// Mitsubishi GX Works2 project: TR3FB_sample_RDLOOPCmd   PLC: Q03UDV
// TR3FBサンプルプログラム シリアル接続 RDLoopCmd制御

PROGRAM MAIN
VAR
  Initial_1 : P+TAKAYA-TR3-C24_Initial;
  RDLOOPCmd_1 : P+TAKAYA-TR3-C24_RDLOOPCmd;
  SetActionMode_1 : P+TAKAYA-TR3-C24_SetActionMode;
  Response_1 : P+TAKAYA-TR3-C24_Response;
END_VAR
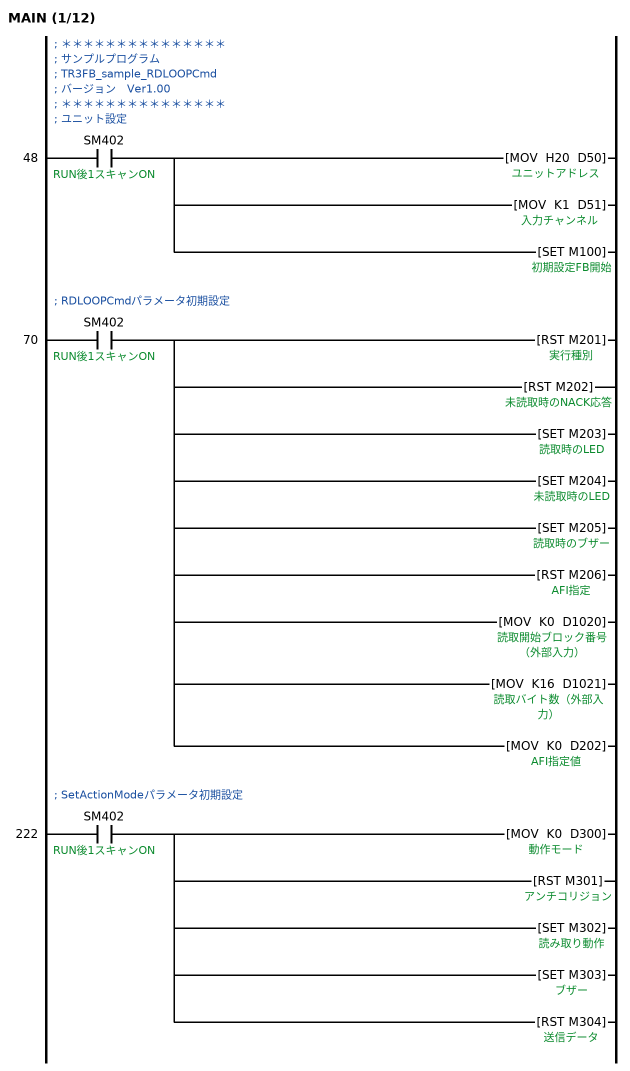
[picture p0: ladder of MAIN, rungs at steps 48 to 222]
; 
; ＊＊＊＊＊＊＊＊＊＊＊＊＊＊＊
; サンプルプログラム
; TR3FB_sample_RDLOOPCmd
; バージョン　Ver1.00
; ＊＊＊＊＊＊＊＊＊＊＊＊＊＊＊
; ユニット設定
48    LD      SM402  ; RUN後1スキャンON
      MOV     H20 D50  ; ユニットアドレス
      MOV     K1 D51  ; 入力チャンネル
      SET     M100  ; 初期設定FB開始
; RDLOOPCmdパラメータ初期設定
70    LD      SM402  ; RUN後1スキャンON
      RST     M201  ; 実行種別
        [note] 実行種別：OFF=RDLOOPモードに遷移
      RST     M202  ; 未読取時のNACK応答
        [note] 未読取時のNACK：OFF=返さない
      SET     M203  ; 読取時のLED
        [note] 読取時LED：ON=点灯
      SET     M204  ; 未読取時のLED
        [note] 未読取時のLED：ON=点灯
      SET     M205  ; 読取時のブザー
        [note] 読取時のブザー：ON=鳴らす
      RST     M206  ; AFI指定
        [note] AFI指定：OFF=AFI値を指定しない
      MOV     K0 D1020  ; 読取開始ブロック番号（外部入力）
        [note] 読取開始ブロック番号=0
      MOV     K16 D1021  ; 読取バイト数（外部入力）
        [note] 読取バイト数=16
      MOV     K0 D202  ; AFI指定値
        [note] AFI指定値=0
; SetActionModeパラメータ初期設定
222   LD      SM402  ; RUN後1スキャンON
      MOV     K0 D300  ; 動作モード
        [note] 動作モード=0x00/コマンドモード
      RST     M301  ; アンチコリジョン
        [note] アンチコリジョン：OFF=無効
      SET     M302  ; 読み取り動作
        [note] 読み取り動作：ON=連続読み取り
      SET     M303  ; ブザー
        [note] ブザー：ON=鳴らす
      RST     M304  ; 送信データ
        [note] 送信データ：OFF=ユーザデータ
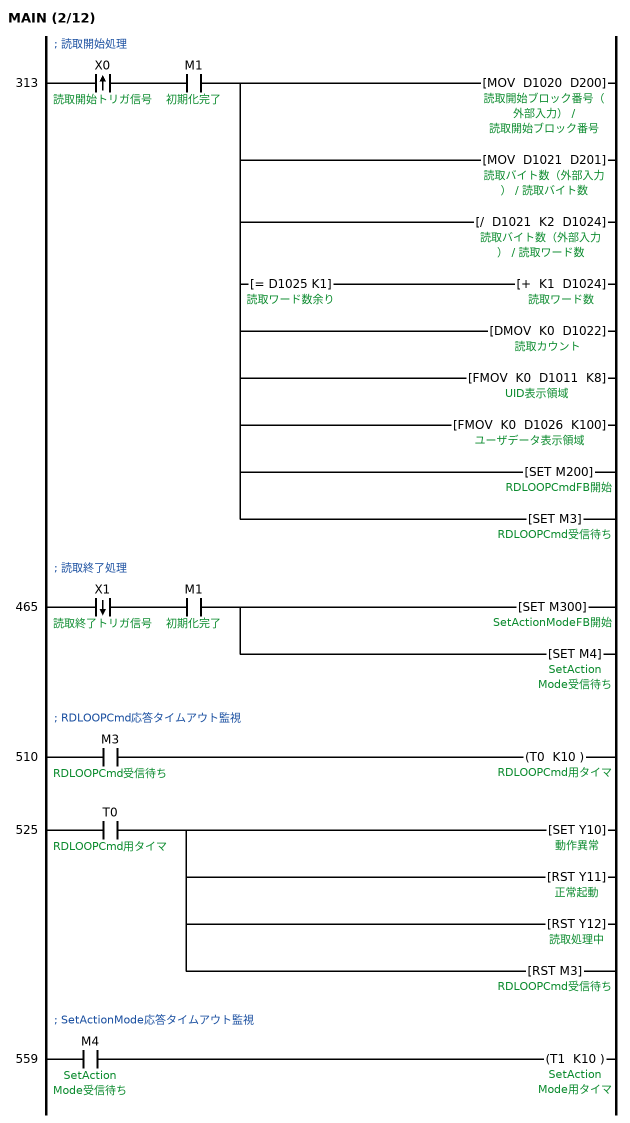
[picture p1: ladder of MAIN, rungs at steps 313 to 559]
; 読取開始処理
313   LDP     X0  ; 読取開始トリガ信号
      AND     M1  ; 初期化完了
      MOV     D1020 D200  ; 読取開始ブロック番号
        [note] 読取開始ブロック番号再設定
      MOV     D1021 D201  ; 読取バイト数
        [note] 読取バイト数再設定
      /       D1021 K2 D1024  ; 読取ワード数
        [note] 読取バイト数から読取ワード数算出
      MPS
      AND=    D1025 K1  ; 読取ワード数余り
      +       K1 D1024
        [note] 余りがあれば1加える
      MPP
      DMOV    K0 D1022  ; 読取カウント
        [note] カウント値クリア
      FMOV    K0 D1011 K8  ; UID表示領域
        [note] UID表示領域クリア
      FMOV    K0 D1026 K100  ; ユーザデータ表示領域
        [note] ユーザデータ表示領域クリア
      SET     M200  ; RDLOOPCmdFB開始
        [note] RDLOOPCmd実行
      SET     M3  ; RDLOOPCmd受信待ち
        [note] 受信待ちフラグセット
; 読取終了処理
465   LDF     X1  ; 読取終了トリガ信号
      AND     M1  ; 初期化完了
      SET     M300  ; SetActionModeFB開始
        [note] SetActionMode実行
      SET     M4  ; SetActionMode受信待ち
        [note] 受信待ちフラグセット
; RDLOOPCmd応答タイムアウト監視
510   LD      M3  ; RDLOOPCmd受信待ち
      OUT     T0 K10  ; RDLOOPCmd用タイマ
        [note] タイマ1秒に設定
525   LD      T0  ; RDLOOPCmd用タイマ
      SET     Y10  ; 動作異常
        [note] タイムアウト処理
      RST     Y11  ; 正常起動
      RST     Y12  ; 読取処理中
      RST     M3  ; RDLOOPCmd受信待ち
; SetActionMode応答タイムアウト監視
559   LD      M4  ; SetActionMode受信待ち
      OUT     T1 K10  ; SetActionMode用タイマ
        [note] タイマ1秒に設定
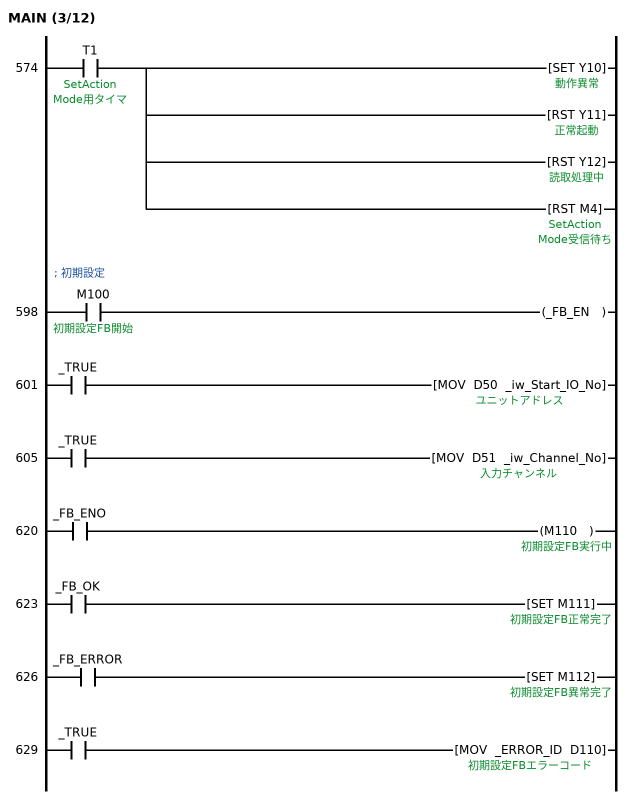
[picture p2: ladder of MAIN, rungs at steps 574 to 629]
574   LD      T1  ; SetActionMode用タイマ
      SET     Y10  ; 動作異常
        [note] タイムアウト処理
      RST     Y11  ; 正常起動
      RST     Y12  ; 読取処理中
      RST     M4  ; SetActionMode受信待ち
; FB BLK START P+TAKAYA-TR3-C24_Initial(Initial_1)
; 
; 初期設定
598   LD      M100  ; 初期設定FB開始
      OUT     _FB_EN
601   LD      _TRUE
      MOV     D50 _iw_Start_IO_No
605   LD      _TRUE
      MOV     D51 _iw_Channel_No
; FB START
; FB_NAME P+TAKAYA-TR3-C24_Initial
; INSTANCE_NAME Initial_1
; FB IN_B:FB_EN
; FB OUT_FB_ENO:B
; FB IN_W:iw_Start_IO_No
; FB OUT_FB_OK:B
; FB IN_W:iw_Channel_No
; FB OUT_FB_ERROR:B
; FB OUT_ERROR_ID:W
; FB END
620   LD      _FB_ENO
      OUT     M110  ; 初期設定FB実行中
623   LD      _FB_OK
      SET     M111  ; 初期設定FB正常完了
626   LD      _FB_ERROR
      SET     M112  ; 初期設定FB異常完了
629   LD      _TRUE
      MOV     _ERROR_ID D110  ; 初期設定FBエラーコード
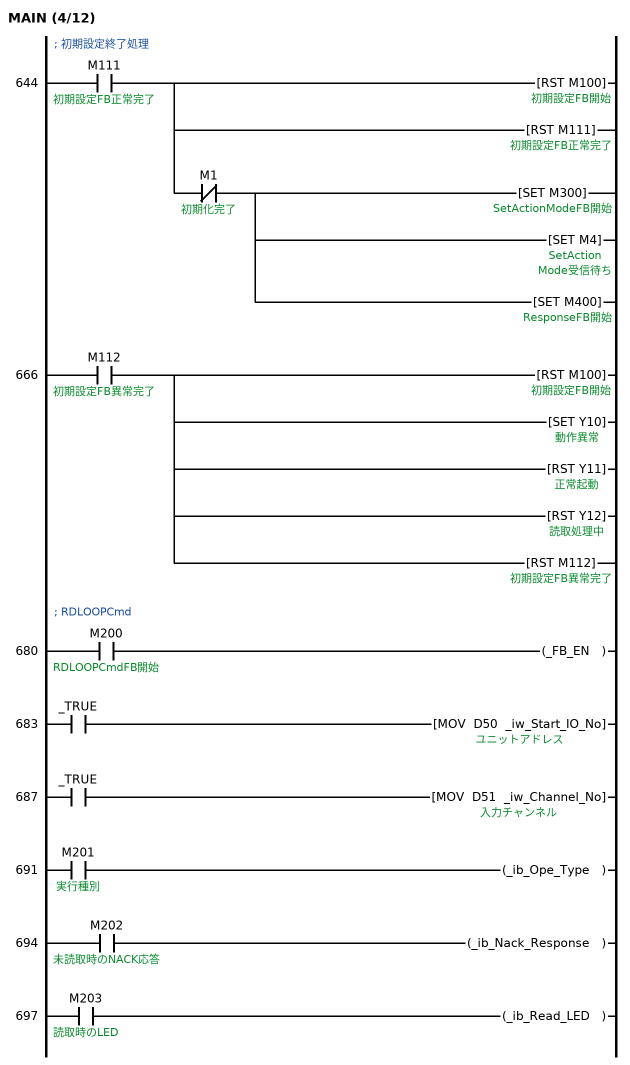
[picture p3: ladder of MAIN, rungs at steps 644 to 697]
; FB BLK END
; 初期設定終了処理
644   LD      M111  ; 初期設定FB正常完了
      RST     M100  ; 初期設定FB開始
      RST     M111  ; 初期設定FB正常完了
      ANI     M1  ; 初期化完了
      SET     M300  ; SetActionModeFB開始
        [note] 起動時コマンドモードに戻す
      SET     M4  ; SetActionMode受信待ち
      SET     M400  ; ResponseFB開始
666   LD      M112  ; 初期設定FB異常完了
      RST     M100  ; 初期設定FB開始
      SET     Y10  ; 動作異常
      RST     Y11  ; 正常起動
      RST     Y12  ; 読取処理中
      RST     M112  ; 初期設定FB異常完了
; FB BLK START P+TAKAYA-TR3-C24_RDLOOPCmd(RDLOOPCmd_1)
; RDLOOPCmd
680   LD      M200  ; RDLOOPCmdFB開始
      OUT     _FB_EN
683   LD      _TRUE
      MOV     D50 _iw_Start_IO_No
687   LD      _TRUE
      MOV     D51 _iw_Channel_No
691   LD      M201  ; 実行種別
      OUT     _ib_Ope_Type
694   LD      M202  ; 未読取時のNACK応答
      OUT     _ib_Nack_Response
697   LD      M203  ; 読取時のLED
      OUT     _ib_Read_LED
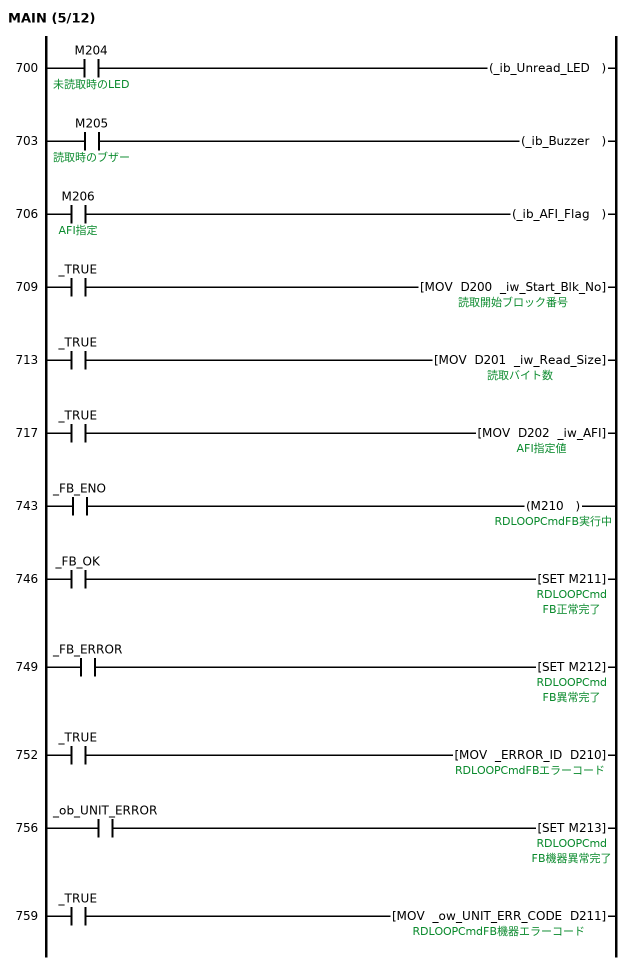
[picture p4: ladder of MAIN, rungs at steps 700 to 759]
700   LD      M204  ; 未読取時のLED
      OUT     _ib_Unread_LED
703   LD      M205  ; 読取時のブザー
      OUT     _ib_Buzzer
706   LD      M206  ; AFI指定
      OUT     _ib_AFI_Flag
709   LD      _TRUE
      MOV     D200 _iw_Start_Blk_No
713   LD      _TRUE
      MOV     D201 _iw_Read_Size
717   LD      _TRUE
      MOV     D202 _iw_AFI
; FB START
; FB_NAME P+TAKAYA-TR3-C24_RDLOOPCmd
; INSTANCE_NAME RDLOOPCmd_1
; FB IN_B:FB_EN
; FB OUT_FB_ENO:B
; FB IN_W:iw_Start_IO_No
; FB OUT_FB_OK:B
; FB IN_W:iw_Channel_No
; FB OUT_FB_ERROR:B
; FB IN_B:ib_Ope_Type
; FB OUT_ERROR_ID:W
; FB IN_B:ib_Nack_Response
; FB OUT_ob_UNIT_ERROR:B
; FB IN_B:ib_Read_LED
; FB OUT_ow_UNIT_ERR_CODE:W
; FB IN_B:ib_Unread_LED
; FB IN_B:ib_Buzzer
; FB IN_B:ib_AFI_Flag
; FB IN_W:iw_Start_Blk_No
; FB IN_W:iw_Read_Size
; FB IN_W:iw_AFI
; FB END
743   LD      _FB_ENO
      OUT     M210  ; RDLOOPCmdFB実行中
746   LD      _FB_OK
      SET     M211  ; RDLOOPCmdFB正常完了
749   LD      _FB_ERROR
      SET     M212  ; RDLOOPCmdFB異常完了
752   LD      _TRUE
      MOV     _ERROR_ID D210  ; RDLOOPCmdFBエラーコード
756   LD      _ob_UNIT_ERROR
      SET     M213  ; RDLOOPCmdFB機器異常完了
759   LD      _TRUE
      MOV     _ow_UNIT_ERR_CODE D211  ; RDLOOPCmdFB機器エラーコード
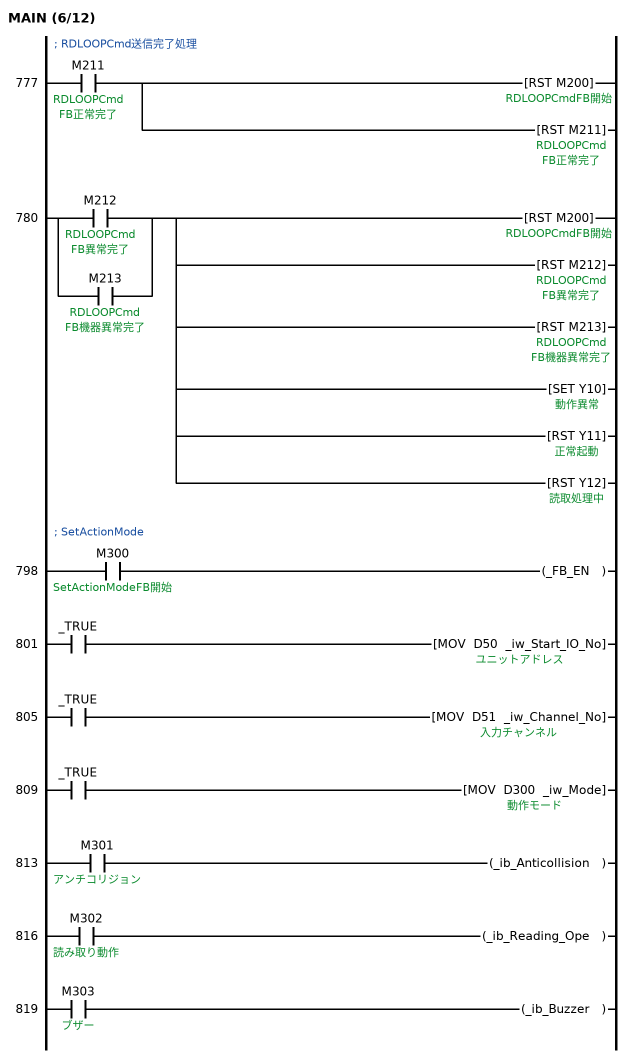
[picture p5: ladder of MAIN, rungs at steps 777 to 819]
; FB BLK END
; RDLOOPCmd送信完了処理
777   LD      M211  ; RDLOOPCmdFB正常完了
      RST     M200  ; RDLOOPCmdFB開始
      RST     M211  ; RDLOOPCmdFB正常完了
780   LD      M212  ; RDLOOPCmdFB異常完了
      OR      M213  ; RDLOOPCmdFB機器異常完了
      RST     M200  ; RDLOOPCmdFB開始
      RST     M212  ; RDLOOPCmdFB異常完了
      RST     M213  ; RDLOOPCmdFB機器異常完了
      SET     Y10  ; 動作異常
      RST     Y11  ; 正常起動
      RST     Y12  ; 読取処理中
; FB BLK START P+TAKAYA-TR3-C24_SetActionMode(SetActionMode_1)
; SetActionMode
798   LD      M300  ; SetActionModeFB開始
      OUT     _FB_EN
801   LD      _TRUE
      MOV     D50 _iw_Start_IO_No
805   LD      _TRUE
      MOV     D51 _iw_Channel_No
809   LD      _TRUE
      MOV     D300 _iw_Mode
813   LD      M301  ; アンチコリジョン
      OUT     _ib_Anticollision
816   LD      M302  ; 読み取り動作
      OUT     _ib_Reading_Ope
819   LD      M303  ; ブザー
      OUT     _ib_Buzzer
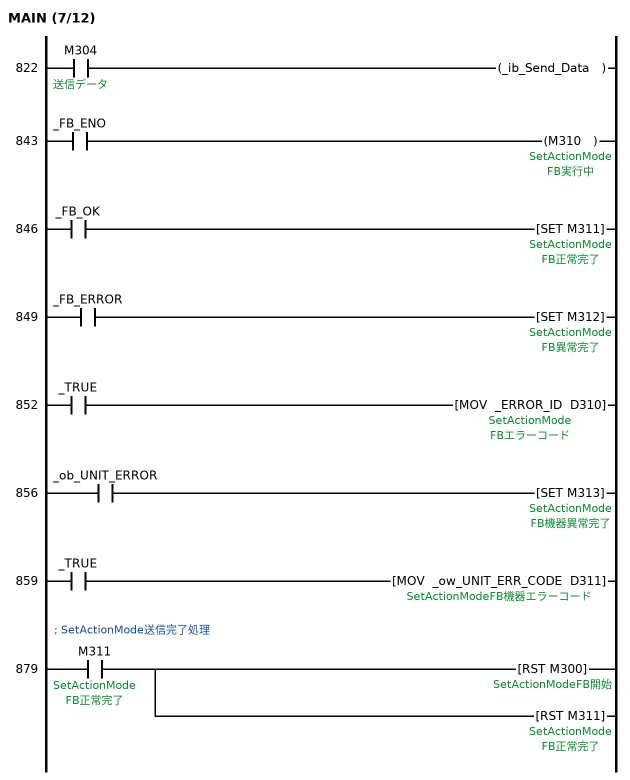
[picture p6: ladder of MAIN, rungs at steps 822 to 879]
822   LD      M304  ; 送信データ
      OUT     _ib_Send_Data
; FB START
; FB_NAME P+TAKAYA-TR3-C24_SetActionMode
; INSTANCE_NAME SetActionMode_1
; FB IN_B:FB_EN
; FB OUT_FB_ENO:B
; FB IN_W:iw_Start_IO_No
; FB OUT_FB_OK:B
; FB IN_W:iw_Channel_No
; FB OUT_FB_ERROR:B
; FB IN_W:iw_Mode
; FB OUT_ERROR_ID:W
; FB IN_B:ib_Anticollision
; FB OUT_ob_UNIT_ERROR:B
; FB IN_B:ib_Reading_Ope
; FB OUT_ow_UNIT_ERR_CODE:W
; FB IN_B:ib_Buzzer
; FB IN_B:ib_Send_Data
; FB END
843   LD      _FB_ENO
      OUT     M310  ; SetActionModeFB実行中
846   LD      _FB_OK
      SET     M311  ; SetActionModeFB正常完了
849   LD      _FB_ERROR
      SET     M312  ; SetActionModeFB異常完了
852   LD      _TRUE
      MOV     _ERROR_ID D310  ; SetActionModeFBエラーコード
856   LD      _ob_UNIT_ERROR
      SET     M313  ; SetActionModeFB機器異常完了
859   LD      _TRUE
      MOV     _ow_UNIT_ERR_CODE D311  ; SetActionModeFB機器エラーコード
; FB BLK END
; SetActionMode送信完了処理
879   LD      M311  ; SetActionModeFB正常完了
      RST     M300  ; SetActionModeFB開始
      RST     M311  ; SetActionModeFB正常完了
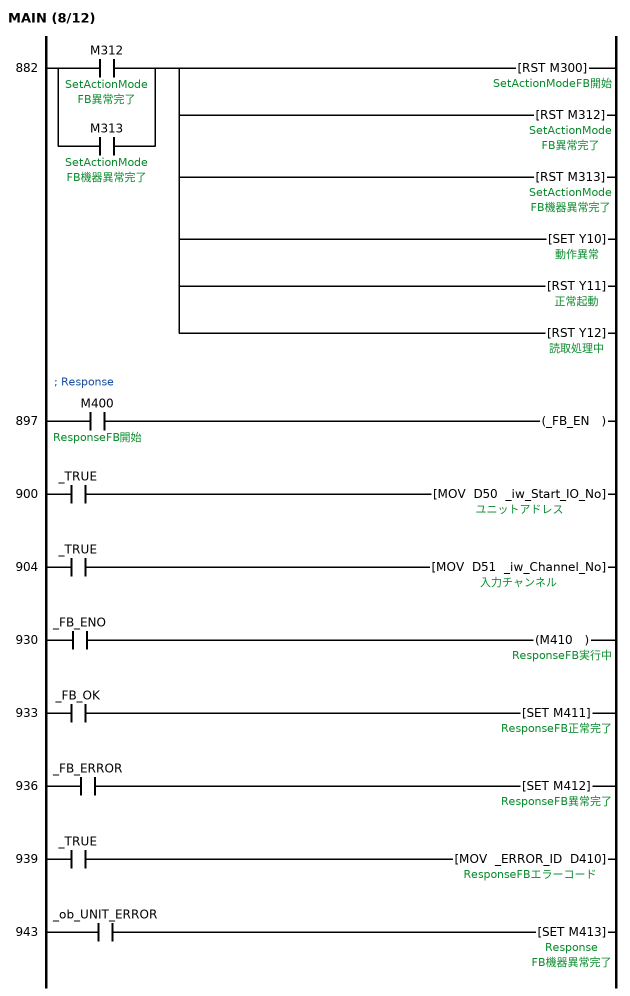
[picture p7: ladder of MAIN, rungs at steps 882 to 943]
882   LD      M312  ; SetActionModeFB異常完了
      OR      M313  ; SetActionModeFB機器異常完了
      RST     M300  ; SetActionModeFB開始
      RST     M312  ; SetActionModeFB異常完了
      RST     M313  ; SetActionModeFB機器異常完了
      SET     Y10  ; 動作異常
      RST     Y11  ; 正常起動
      RST     Y12  ; 読取処理中
; FB BLK START P+TAKAYA-TR3-C24_Response(Response_1)
; Response
897   LD      M400  ; ResponseFB開始
      OUT     _FB_EN
900   LD      _TRUE
      MOV     D50 _iw_Start_IO_No
904   LD      _TRUE
      MOV     D51 _iw_Channel_No
; FB START
; FB_NAME P+TAKAYA-TR3-C24_Response
; INSTANCE_NAME Response_1
; FB IN_B:FB_EN
; FB OUT_FB_ENO:B
; FB IN_W:iw_Start_IO_No
; FB OUT_FB_OK:B
; FB IN_W:iw_Channel_No
; FB OUT_FB_ERROR:B
; FB OUT_ERROR_ID:W
; FB OUT_ob_UNIT_ERROR:B
; FB OUT_ow_UNT_ERR_CODE1:W
; FB OUT_ow_UNT_ERR_CODE2:W
; FB OUT_ow_RFID_Res_Type:W
; FB OUT_ow_RFID_ID:W
; FB OUT_ow_RFID_UID_Len:W
; FB OUT_ow_RFID_Data_Len:W
; FB OUT_ow_RFID_UII_Len:W
; FB OUT_owa_RFID_UID:W
; FB OUT_owa_RFID_Data:W
; FB OUT_owa_RFID_UII:W
; FB END
930   LD      _FB_ENO
      OUT     M410  ; ResponseFB実行中
933   LD      _FB_OK
      SET     M411  ; ResponseFB正常完了
936   LD      _FB_ERROR
      SET     M412  ; ResponseFB異常完了
939   LD      _TRUE
      MOV     _ERROR_ID D410  ; ResponseFBエラーコード
943   LD      _ob_UNIT_ERROR
      SET     M413  ; ResponseFB機器異常完了
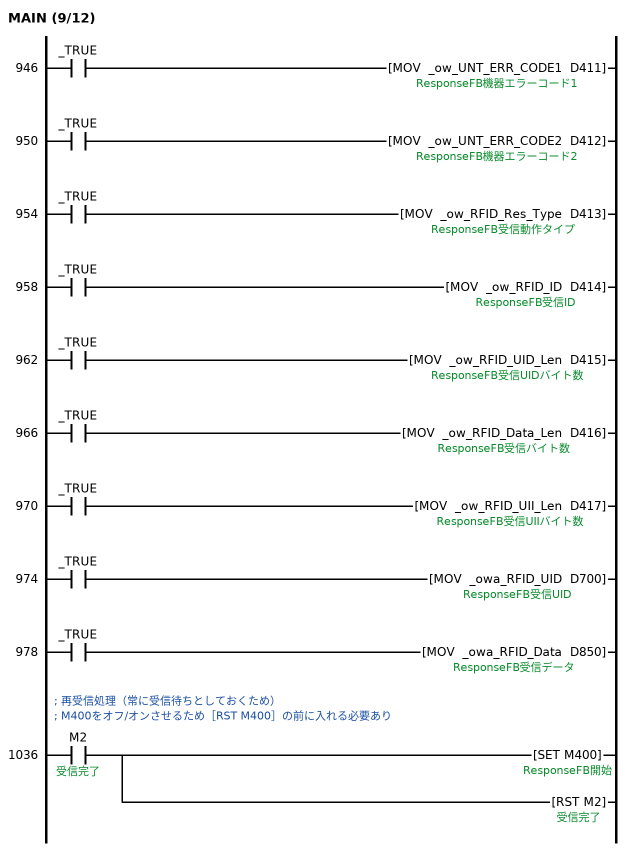
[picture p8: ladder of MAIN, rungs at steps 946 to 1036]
946   LD      _TRUE
      MOV     _ow_UNT_ERR_CODE1 D411  ; ResponseFB機器エラーコード1
950   LD      _TRUE
      MOV     _ow_UNT_ERR_CODE2 D412  ; ResponseFB機器エラーコード2
954   LD      _TRUE
      MOV     _ow_RFID_Res_Type D413  ; ResponseFB受信動作タイプ
958   LD      _TRUE
      MOV     _ow_RFID_ID D414  ; ResponseFB受信ID
962   LD      _TRUE
      MOV     _ow_RFID_UID_Len D415  ; ResponseFB受信UIDバイト数
966   LD      _TRUE
      MOV     _ow_RFID_Data_Len D416  ; ResponseFB受信バイト数
970   LD      _TRUE
      MOV     _ow_RFID_UII_Len D417  ; ResponseFB受信UIIバイト数
974   LD      _TRUE
      MOV     _owa_RFID_UID D700  ; ResponseFB受信UID
978   LD      _TRUE
      MOV     _owa_RFID_Data D850  ; ResponseFB受信データ
; FB BLK END
; 再受信処理（常に受信待ちとしておくため）
; M400をオフ/オンさせるため［RST M400］の前に入れる必要あり
1036  LD      M2  ; 受信完了
      SET     M400  ; ResponseFB開始
      RST     M2  ; 受信完了
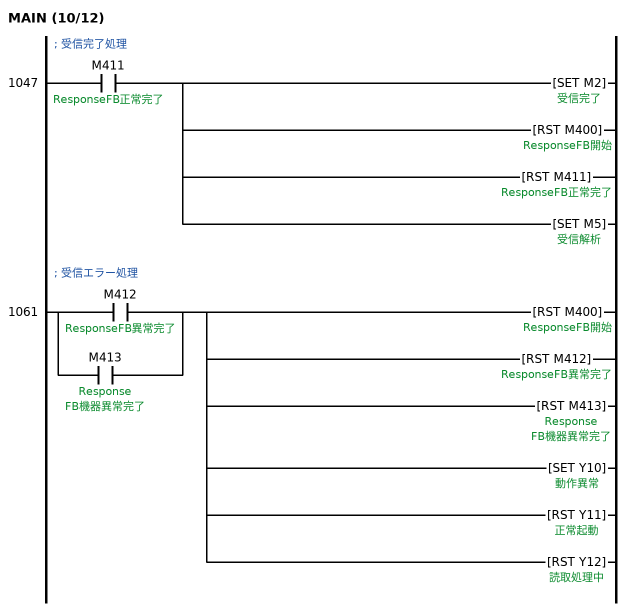
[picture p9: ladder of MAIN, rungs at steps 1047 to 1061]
; 受信完了処理
1047  LD      M411  ; ResponseFB正常完了
      SET     M2  ; 受信完了
      RST     M400  ; ResponseFB開始
      RST     M411  ; ResponseFB正常完了
      SET     M5  ; 受信解析
; 受信エラー処理
1061  LD      M412  ; ResponseFB異常完了
      OR      M413  ; ResponseFB機器異常完了
      RST     M400  ; ResponseFB開始
      RST     M412  ; ResponseFB異常完了
      RST     M413  ; ResponseFB機器異常完了
      SET     Y10  ; 動作異常
      RST     Y11  ; 正常起動
      RST     Y12  ; 読取処理中
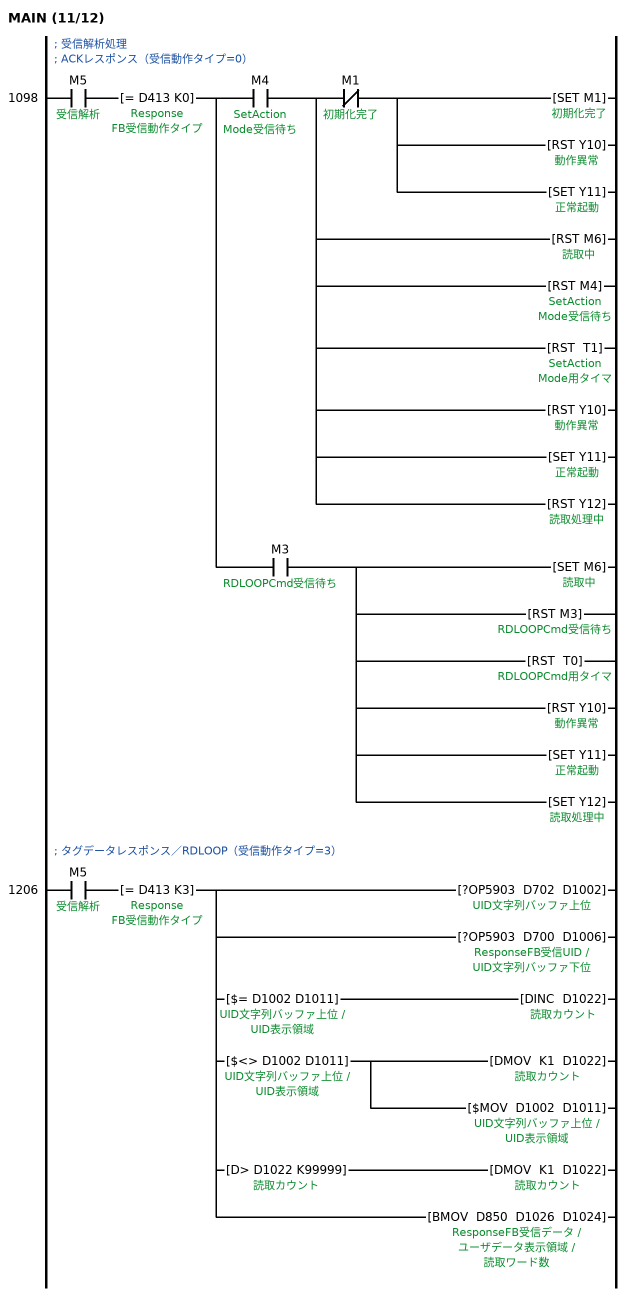
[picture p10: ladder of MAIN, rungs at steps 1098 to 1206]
; 
; 受信解析処理
; ACKレスポンス（受信動作タイプ=0）
1098  LD      M5  ; 受信解析
      AND=    D413 K0  ; ResponseFB受信動作タイプ
      MPS
      AND     M4  ; SetActionMode受信待ち
      MPS
      ANI     M1  ; 初期化完了
      SET     M1  ; 初期化完了
        [note] SetActionModeのACK
      RST     Y10  ; 動作異常
      SET     Y11  ; 正常起動
      MPP
      RST     M6  ; 読取中
      RST     M4  ; SetActionMode受信待ち
      RST     T1  ; SetActionMode用タイマ
        [note] 正常処理のためタイマクリア
      RST     Y10  ; 動作異常
      SET     Y11  ; 正常起動
      RST     Y12  ; 読取処理中
      MPP
      AND     M3  ; RDLOOPCmd受信待ち
      SET     M6  ; 読取中
        [note] RDLOOPCmdのACK
      RST     M3  ; RDLOOPCmd受信待ち
      RST     T0  ; RDLOOPCmd用タイマ
        [note] 正常処理のためタイマクリア
      RST     Y10  ; 動作異常
      SET     Y11  ; 正常起動
      SET     Y12  ; 読取処理中
; タグデータレスポンス／RDLOOP（受信動作タイプ=3）
1206  LD      M5  ; 受信解析
      AND=    D413 K3  ; ResponseFB受信動作タイプ
      ?OP5903 D702 D1002  ; UID文字列バッファ上位
        [note] UID上位をHEX文字列でGOTに表示
      ?OP5903 D700 D1006  ; UID文字列バッファ下位
        [note] UID下位をHEX文字列でGOTに表示
      MPS
      AND$=   D1002 D1011  ; UID文字列バッファ上位 / UID表示領域
      DINC    D1022
        [note] UIDが同じならカウント数インクリ
      MRD
      AND$<>  D1002 D1011  ; UID文字列バッファ上位 / UID表示領域
      DMOV    K1 D1022
        [note] UIDが異なる場合カウント値=1
      $MOV    D1002 D1011
        [note] UIDデータをHEX文字列でGOTに表示
      MRD
      ANDD>   D1022 K99999  ; 読取カウント
      DMOV    K1 D1022
        [note] カウント値>99999で1にリセット
      MPP
      BMOV    D850 D1026 D1024
        [note] ユーザデータ表示
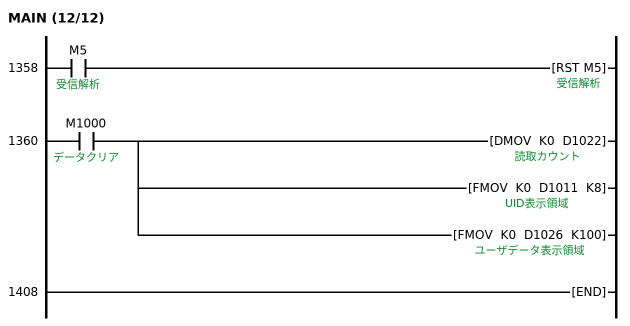
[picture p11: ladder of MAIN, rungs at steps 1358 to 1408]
1358  LD      M5  ; 受信解析
      RST     M5  ; 受信解析
1360  LD      M1000  ; データクリア
      DMOV    K0 D1022
        [note] カウント値クリア
      FMOV    K0 D1011 K8
        [note] UID表示領域クリア
      FMOV    K0 D1026 K100
        [note] ユーザデータ表示領域クリア
1408  END
END_PROGRAM

FUNCTION_BLOCK P+TAKAYA-TR3-C24_Initial  // 初期設定
VAR_INPUT
  FB_EN : BOOL;  (* 実行命令 *)
  iw_Start_IO_No : INT;  (* ユニット装着XYアドレス *)
  iw_Channel_No : INT;  (* 入力チャンネル *)
END_VAR
VAR_OUTPUT
  FB_ENO : BOOL;  (* 実行状態 *)
  FB_OK : BOOL;  (* 正常完了 *)
  FB_ERROR : BOOL;  (* 異常完了フラグ *)
  ERROR_ID : INT;  (* エラーコード *)
END_VAR
VAR
  vb_Program_Init : BOOL;  (* プログラム実行前初期化 *)
  vb_Check_Input : BOOL;  (* 入力範囲判定 *)
  vb_Module_Init : BOOL;  (* ユニット初期化 *)
  vb_Program_End : BOOL;  (* FB終了処理内部フラグ *)
  vb_Tmp_OK : BOOL;  (* FB完了内部フラグ *)
  vb_Tmp_Error : BOOL;  (* エラー内部フラグ *)
  vw_Start_IO_No_Tmp : INT;  (* ユニット装着XYアドレス内部 *)
  vw_Channel_No_Tmp : INT;  (* 入力チャンネル内部 *)
  vw_ZTmp1 : INT;  (* Zデバイス1内部 *)
  vw_ZTmp2 : INT;  (* Zデバイス2内部 *)
END_VAR
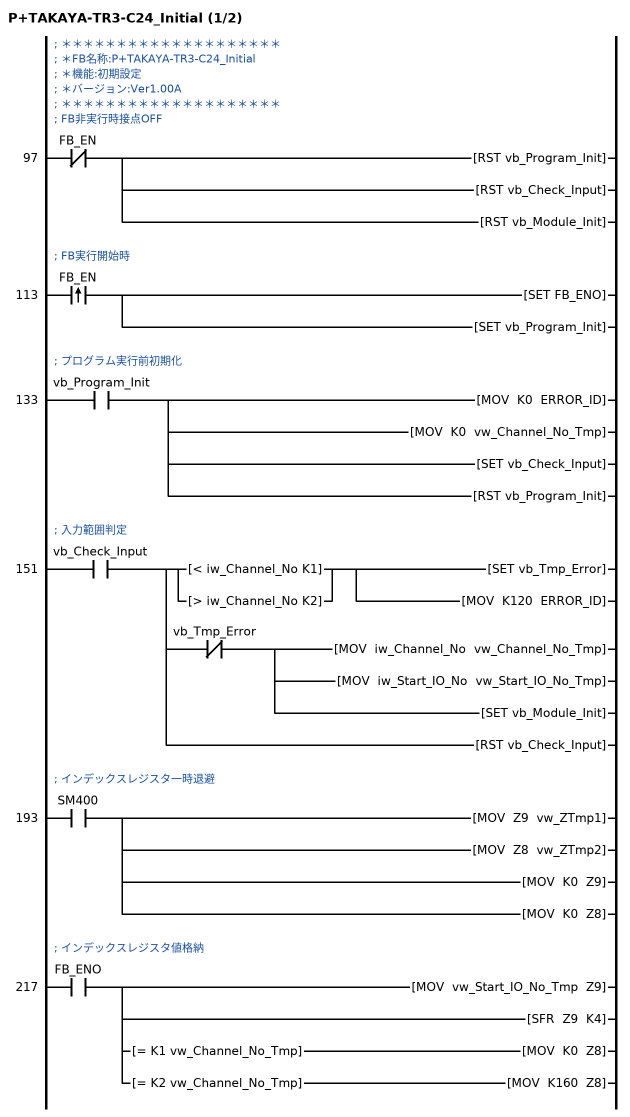
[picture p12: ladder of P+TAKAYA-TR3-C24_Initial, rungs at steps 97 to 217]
; ＊＊＊＊＊＊＊＊＊＊＊＊＊＊＊＊＊＊＊＊
; ＊FB名称:P+TAKAYA-TR3-C24_Initial
; ＊機能:初期設定
; ＊バージョン:Ver1.00A
; ＊＊＊＊＊＊＊＊＊＊＊＊＊＊＊＊＊＊＊＊
; FB非実行時接点OFF
97    LDI     FB_EN
      RST     vb_Program_Init
      RST     vb_Check_Input
      RST     vb_Module_Init
; FB実行開始時
113   LDP     FB_EN
      SET     FB_ENO
      SET     vb_Program_Init
; プログラム実行前初期化
133   LD      vb_Program_Init
      MOV     K0 ERROR_ID
      MOV     K0 vw_Channel_No_Tmp
      SET     vb_Check_Input
      RST     vb_Program_Init
; 入力範囲判定
151   LD      vb_Check_Input
      MPS
      LD<     iw_Channel_No K1
      OR>     iw_Channel_No K2
      ANB
      SET     vb_Tmp_Error
      MOV     K120 ERROR_ID
      MRD
      ANI     vb_Tmp_Error
      MOV     iw_Channel_No vw_Channel_No_Tmp
      MOV     iw_Start_IO_No vw_Start_IO_No_Tmp
      SET     vb_Module_Init
      MPP
      RST     vb_Check_Input
; インデックスレジスタ一時退避
193   LD      SM400
      MOV     Z9 vw_ZTmp1
      MOV     Z8 vw_ZTmp2
      MOV     K0 Z9
      MOV     K0 Z8
; インデックスレジスタ値格納
217   LD      FB_ENO
      MOV     vw_Start_IO_No_Tmp Z9
      SFR     Z9 K4
      MPS
      AND=    K1 vw_Channel_No_Tmp
      MOV     K0 Z8
      MPP
      AND=    K2 vw_Channel_No_Tmp
      MOV     K160 Z8
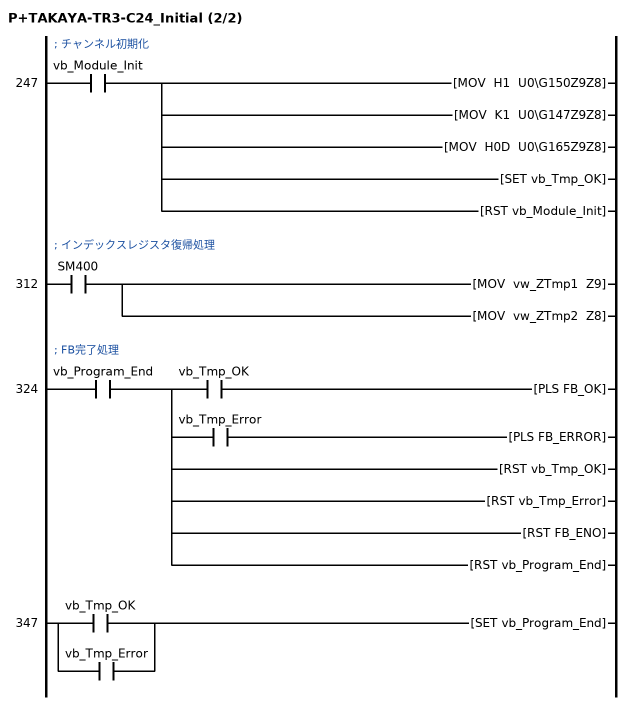
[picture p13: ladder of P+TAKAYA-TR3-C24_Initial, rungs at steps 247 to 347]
; チャンネル初期化
247   LD      vb_Module_Init
      MOV     H1 U0\G150Z9Z8
        [note] バイト単位指定
      MOV     K1 U0\G147Z9Z8
        [note] DC制御指定
      MOV     H0D U0\G165Z9Z8
        [note] 受信終了コード
      SET     vb_Tmp_OK
      RST     vb_Module_Init
; インデックスレジスタ復帰処理
312   LD      SM400
      MOV     vw_ZTmp1 Z9
      MOV     vw_ZTmp2 Z8
; FB完了処理
324   LD      vb_Program_End
      MPS
      AND     vb_Tmp_OK
      PLS     FB_OK
      MRD
      AND     vb_Tmp_Error
      PLS     FB_ERROR
      MPP
      RST     vb_Tmp_OK
      RST     vb_Tmp_Error
      RST     FB_ENO
      RST     vb_Program_End
347   LD      vb_Tmp_OK
      OR      vb_Tmp_Error
      SET     vb_Program_End
END_FUNCTION_BLOCK

FUNCTION_BLOCK P+TAKAYA-TR3-C24_RDLOOPCmd  // RDLOOPCmd
VAR_INPUT
  FB_EN : BOOL;  (* 実行命令 *)
END_VAR
VAR_OUTPUT
  FB_OK : BOOL;  (* 正常完了 *)
  FB_ERROR : BOOL;  (* 異常完了フラグ *)
  ERROR_ID : INT;  (* エラーコード *)
  FB_ENO : BOOL;  (* 実行状態 *)
END_VAR
VAR
  vb_Program_Init : BOOL;  (* プログラム実行前初期化 *)
  vb_Check_Input : BOOL;  (* 入力範囲判定 *)
  vb_Tmp_Error : BOOL;  (* エラー内部フラグ *)
  vb_Tmp_OK : BOOL;  (* FB完了内部フラグ *)
  vb_Tmp_Unit_Error : BOOL;  (* 機器エラー内部フラグ *)
  vb_Program_End : BOOL;  (* FB終了処理内部フラグ *)
END_VAR
VAR_OUTPUT
  ob_UNIT_ERROR : BOOL;  (* 機器異常完了フラグ *)
  ow_UNIT_ERR_CODE : INT;  (* 機器エラーコード *)
END_VAR
VAR
  vwa_Control_Data : ARRAY [0..2] OF INT;  (* コントロールデータ *)
  vb_Sum_Calc : BOOL;  (* SUM計算開始フラグ *)
  vb_Send_Ready : BOOL;  (* 送信準備完了フラグ *)
  vwa_Send_Sum : ARRAY [0..1] OF INT;  (* 送信SUM合計値 *)
  vwa_Buff_Send_Byte : ARRAY [0..12] OF INT;  (* 送信バッファバイト *)
  vba_Send : ARRAY [0..2] OF BOOL;  (* 送信処理フラグ *)
END_VAR
VAR_INPUT
  iw_Start_Blk_No : INT;  (* 読み取り開始ブロック番号 *)
END_VAR
VAR
  vw_Cmd_Parameter : INT;  (* コマンドパラメータ *)
  vb_Cmd_Parameter : BOOL;  (* コマンドパラメータ設定 *)
  vw_Start_Blk_No_Tmp : INT;  (* 読み取り開始ブロック番号内部 *)
  vb_Join_Byte : BOOL;  (* バイト単位結合 *)
  vwa_Buff_Send_Word : ARRAY [0..6] OF INT;  (* 送信バッファワード *)
END_VAR
VAR_INPUT
  iw_Read_Size : INT;  (* 読み取りバイト数 *)
END_VAR
VAR
  vw_Read_Size_Tmp : INT;  (* 読み取りバイト数内部 *)
END_VAR
VAR_INPUT
  iw_AFI : INT;  (* AFI指定値 *)
END_VAR
VAR
  vw_AFI_Tmp : INT;  (* AFI指定値内部 *)
END_VAR
VAR_INPUT
  ib_Ope_Type : BOOL;  (* 実行種別 *)
  ib_Nack_Response : BOOL;  (* 未読み取り時のNACK応答 *)
  ib_Read_LED : BOOL;  (* 読み取り時のLED *)
  ib_Unread_LED : BOOL;  (* 未読み取り時のLED *)
  ib_Buzzer : BOOL;  (* 読み取り時のブザー *)
  ib_AFI_Flag : BOOL;  (* AFI指定 *)
END_VAR
VAR
  vb_RFID_Option : BOOL;  (* RFタグオプションフラグ *)
  vw_RFID_Option_Tmp : INT;  (* RFタグオプション *)
END_VAR
VAR_INPUT
  iw_Start_IO_No : INT;  (* ユニット装着XYアドレス *)
  iw_Channel_No : INT;  (* 入力チャンネル *)
END_VAR
VAR
  vw_Start_IO_No_Tmp : INT;  (* ユニット装着XYアドレス内部 *)
  vw_Channel_No_Tmp : INT;  (* 入力チャンネル内部 *)
  vw_ZTmp1 : INT;  (* Zデバイス1内部 *)
  vb_Make_Control_Data : BOOL;  (* コントロールデータ生成 *)
END_VAR
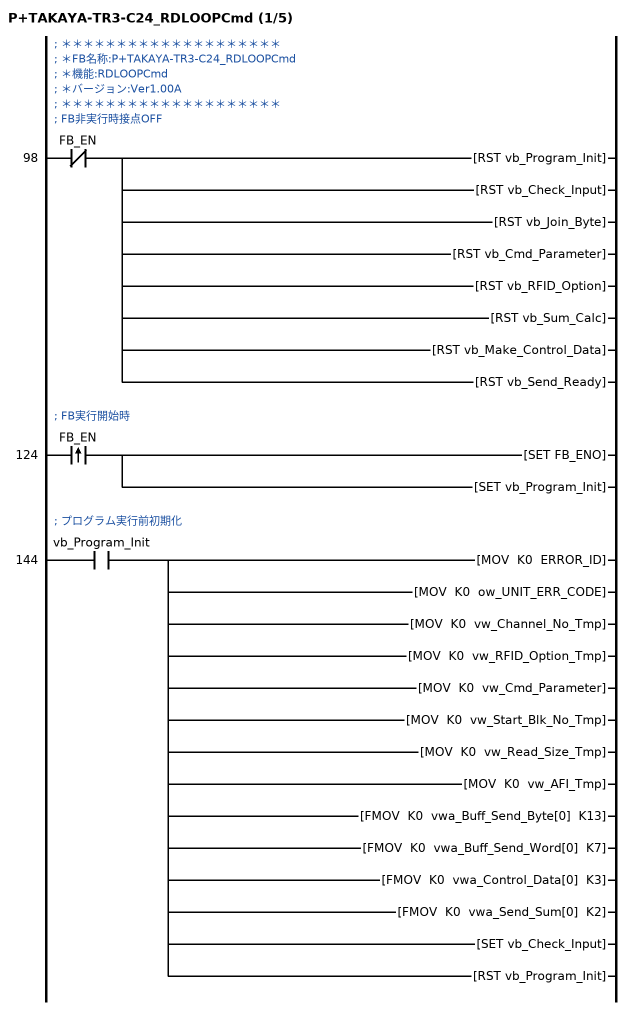
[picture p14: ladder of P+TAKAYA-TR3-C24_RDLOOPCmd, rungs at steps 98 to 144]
; ＊＊＊＊＊＊＊＊＊＊＊＊＊＊＊＊＊＊＊＊
; ＊FB名称:P+TAKAYA-TR3-C24_RDLOOPCmd
; ＊機能:RDLOOPCmd
; ＊バージョン:Ver1.00A
; ＊＊＊＊＊＊＊＊＊＊＊＊＊＊＊＊＊＊＊＊
; FB非実行時接点OFF
98    LDI     FB_EN
      RST     vb_Program_Init
      RST     vb_Check_Input
      RST     vb_Join_Byte
      RST     vb_Cmd_Parameter
      RST     vb_RFID_Option
      RST     vb_Sum_Calc
      RST     vb_Make_Control_Data
      RST     vb_Send_Ready
; FB実行開始時
124   LDP     FB_EN
      SET     FB_ENO
      SET     vb_Program_Init
; プログラム実行前初期化
144   LD      vb_Program_Init
      MOV     K0 ERROR_ID
      MOV     K0 ow_UNIT_ERR_CODE
      MOV     K0 vw_Channel_No_Tmp
      MOV     K0 vw_RFID_Option_Tmp
      MOV     K0 vw_Cmd_Parameter
      MOV     K0 vw_Start_Blk_No_Tmp
      MOV     K0 vw_Read_Size_Tmp
      MOV     K0 vw_AFI_Tmp
      FMOV    K0 vwa_Buff_Send_Byte[0] K13
      FMOV    K0 vwa_Buff_Send_Word[0] K7
      FMOV    K0 vwa_Control_Data[0] K3
      FMOV    K0 vwa_Send_Sum[0] K2
      SET     vb_Check_Input
      RST     vb_Program_Init
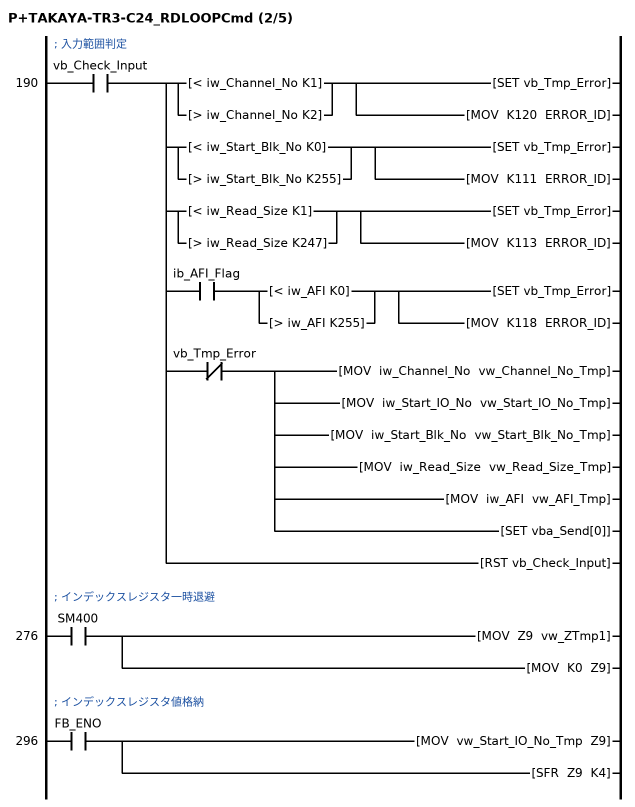
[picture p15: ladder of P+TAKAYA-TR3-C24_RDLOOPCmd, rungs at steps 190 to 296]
; 入力範囲判定
190   LD      vb_Check_Input
      MPS
      LD<     iw_Channel_No K1
      OR>     iw_Channel_No K2
      ANB
      SET     vb_Tmp_Error
      MOV     K120 ERROR_ID
      MRD
      LD<     iw_Start_Blk_No K0
      OR>     iw_Start_Blk_No K255
      ANB
      SET     vb_Tmp_Error
      MOV     K111 ERROR_ID
      MRD
      LD<     iw_Read_Size K1
      OR>     iw_Read_Size K247
      ANB
      SET     vb_Tmp_Error
      MOV     K113 ERROR_ID
      MRD
      AND     ib_AFI_Flag
      LD<     iw_AFI K0
      OR>     iw_AFI K255
      ANB
      SET     vb_Tmp_Error
      MOV     K118 ERROR_ID
      MRD
      ANI     vb_Tmp_Error
      MOV     iw_Channel_No vw_Channel_No_Tmp
      MOV     iw_Start_IO_No vw_Start_IO_No_Tmp
      MOV     iw_Start_Blk_No vw_Start_Blk_No_Tmp
      MOV     iw_Read_Size vw_Read_Size_Tmp
      MOV     iw_AFI vw_AFI_Tmp
      SET     vba_Send[0]
      MPP
      RST     vb_Check_Input
; インデックスレジスタ一時退避
276   LD      SM400
      MOV     Z9 vw_ZTmp1
      MOV     K0 Z9
; インデックスレジスタ値格納
296   LD      FB_ENO
      MOV     vw_Start_IO_No_Tmp Z9
      SFR     Z9 K4
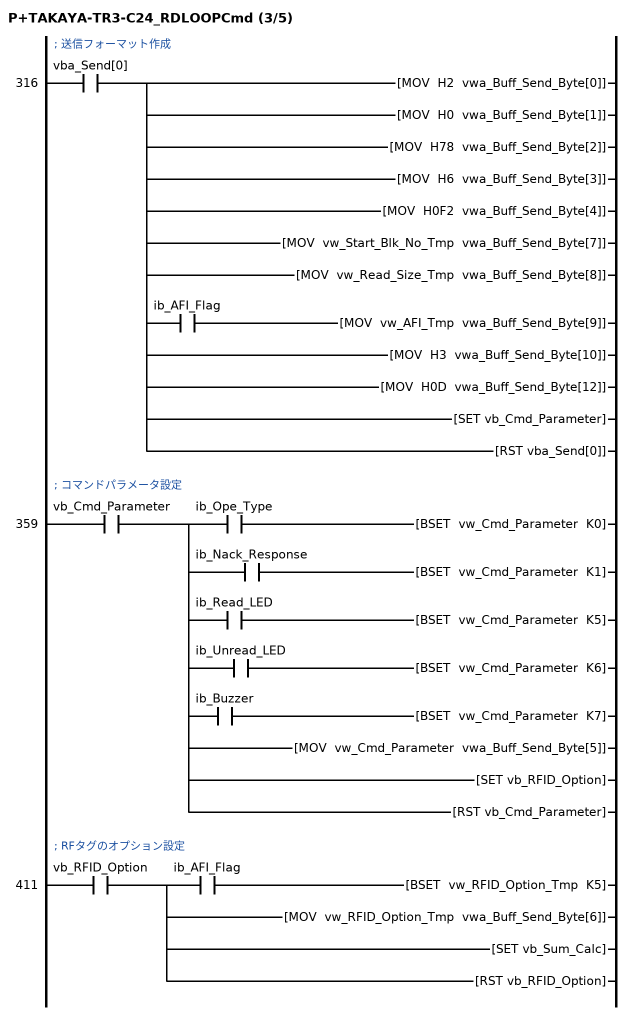
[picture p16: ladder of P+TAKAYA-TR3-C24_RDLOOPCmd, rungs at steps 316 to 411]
; 送信フォーマット作成
316   LD      vba_Send[0]
      MOV     H2 vwa_Buff_Send_Byte[0]
      MOV     H0 vwa_Buff_Send_Byte[1]
      MOV     H78 vwa_Buff_Send_Byte[2]
      MOV     H6 vwa_Buff_Send_Byte[3]
      MOV     H0F2 vwa_Buff_Send_Byte[4]
      MOV     vw_Start_Blk_No_Tmp vwa_Buff_Send_Byte[7]
      MOV     vw_Read_Size_Tmp vwa_Buff_Send_Byte[8]
      MPS
      AND     ib_AFI_Flag
      MOV     vw_AFI_Tmp vwa_Buff_Send_Byte[9]
      MPP
      MOV     H3 vwa_Buff_Send_Byte[10]
      MOV     H0D vwa_Buff_Send_Byte[12]
      SET     vb_Cmd_Parameter
      RST     vba_Send[0]
; コマンドパラメータ設定
359   LD      vb_Cmd_Parameter
      MPS
      AND     ib_Ope_Type
      BSET    vw_Cmd_Parameter K0
      MRD
      AND     ib_Nack_Response
      BSET    vw_Cmd_Parameter K1
      MRD
      AND     ib_Read_LED
      BSET    vw_Cmd_Parameter K5
      MRD
      AND     ib_Unread_LED
      BSET    vw_Cmd_Parameter K6
      MRD
      AND     ib_Buzzer
      BSET    vw_Cmd_Parameter K7
      MPP
      MOV     vw_Cmd_Parameter vwa_Buff_Send_Byte[5]
      SET     vb_RFID_Option
      RST     vb_Cmd_Parameter
; RFタグのオプション設定
411   LD      vb_RFID_Option
      MPS
      AND     ib_AFI_Flag
      BSET    vw_RFID_Option_Tmp K5
      MPP
      MOV     vw_RFID_Option_Tmp vwa_Buff_Send_Byte[6]
      SET     vb_Sum_Calc
      RST     vb_RFID_Option
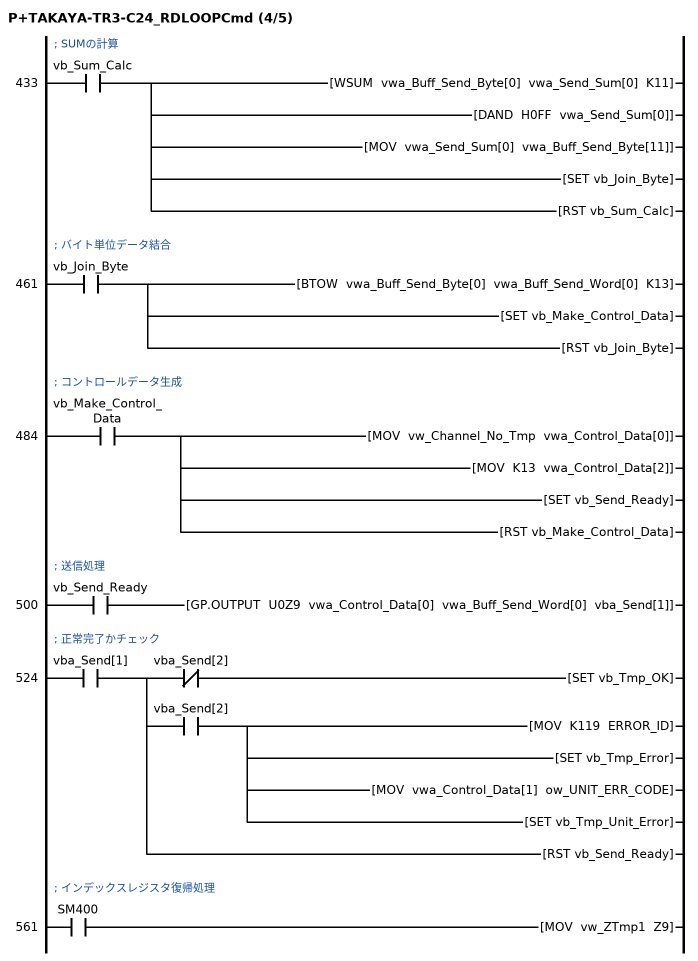
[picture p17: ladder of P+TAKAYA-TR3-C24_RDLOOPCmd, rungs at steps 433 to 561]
; SUMの計算
433   LD      vb_Sum_Calc
      WSUM    vwa_Buff_Send_Byte[0] vwa_Send_Sum[0] K11
      DAND    H0FF vwa_Send_Sum[0]
      MOV     vwa_Send_Sum[0] vwa_Buff_Send_Byte[11]
      SET     vb_Join_Byte
      RST     vb_Sum_Calc
; バイト単位データ結合
461   LD      vb_Join_Byte
      BTOW    vwa_Buff_Send_Byte[0] vwa_Buff_Send_Word[0] K13
      SET     vb_Make_Control_Data
      RST     vb_Join_Byte
; コントロールデータ生成
484   LD      vb_Make_Control_Data
      MOV     vw_Channel_No_Tmp vwa_Control_Data[0]
      MOV     K13 vwa_Control_Data[2]
      SET     vb_Send_Ready
      RST     vb_Make_Control_Data
; 送信処理
500   LD      vb_Send_Ready
      GP.OUTPUT U0Z9 vwa_Control_Data[0] vwa_Buff_Send_Word[0] vba_Send[1]
; 正常完了かチェック
524   LD      vba_Send[1]
      MPS
      ANI     vba_Send[2]
      SET     vb_Tmp_OK
      MRD
      AND     vba_Send[2]
      MOV     K119 ERROR_ID
      SET     vb_Tmp_Error
      MOV     vwa_Control_Data[1] ow_UNIT_ERR_CODE
      SET     vb_Tmp_Unit_Error
      MPP
      RST     vb_Send_Ready
; インデックスレジスタ復帰処理
561   LD      SM400
      MOV     vw_ZTmp1 Z9
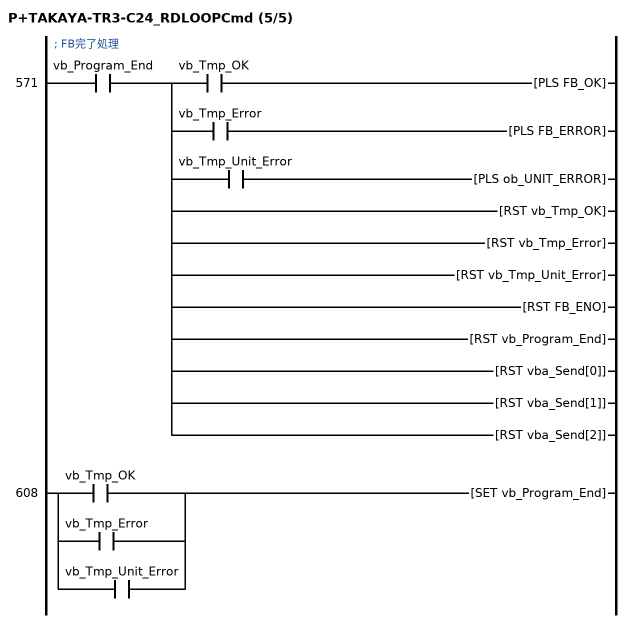
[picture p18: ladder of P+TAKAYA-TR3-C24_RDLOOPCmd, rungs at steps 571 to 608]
; FB完了処理
571   LD      vb_Program_End
      MPS
      AND     vb_Tmp_OK
      PLS     FB_OK
      MRD
      AND     vb_Tmp_Error
      PLS     FB_ERROR
      MRD
      AND     vb_Tmp_Unit_Error
      PLS     ob_UNIT_ERROR
      MPP
      RST     vb_Tmp_OK
      RST     vb_Tmp_Error
      RST     vb_Tmp_Unit_Error
      RST     FB_ENO
      RST     vb_Program_End
      RST     vba_Send[0]
      RST     vba_Send[1]
      RST     vba_Send[2]
608   LD      vb_Tmp_OK
      OR      vb_Tmp_Error
      OR      vb_Tmp_Unit_Error
      SET     vb_Program_End
END_FUNCTION_BLOCK

FUNCTION_BLOCK P+TAKAYA-TR3-C24_Response  // 受信設定
VAR_INPUT
  FB_EN : BOOL;  (* 実行命令 *)
  iw_Start_IO_No : INT;  (* ユニット装着XYアドレス *)
END_VAR
VAR_OUTPUT
  FB_ENO : BOOL;  (* 実行状態 *)
  FB_OK : BOOL;  (* 正常完了 *)
  FB_ERROR : BOOL;  (* 異常完了フラグ *)
  ERROR_ID : INT;  (* エラーコード *)
  ob_UNIT_ERROR : BOOL;  (* 機器異常完了フラグ *)
  ow_UNT_ERR_CODE1 : INT;  (* 機器エラーコード1 *)
  ow_UNT_ERR_CODE2 : INT;  (* 機器エラーコード2 *)
  ow_RFID_Res_Type : INT;  (* 受信動作タイプ *)
  ow_RFID_ID : INT;  (* 受信ID *)
  ow_RFID_UID_Len : INT;  (* 受信UIDバイト数 *)
  ow_RFID_Data_Len : INT;  (* 受信バイト数 *)
  ow_RFID_UII_Len : INT;  (* 受信UIIバイト数 *)
  owa_RFID_UID : INT;  (* 受信UID *)
  owa_RFID_Data : INT;  (* 受信データ *)
  owa_RFID_UII : INT;  (* 受信UII *)
END_VAR
VAR
  vb_Tmp_OK : BOOL;  (* 正常完了内部フラグ *)
  vb_Tmp_Error : BOOL;  (* 異常完了内部フラグ *)
  vb_Tmp_Unit_Error : BOOL;  (* 機器異常完了内部フラグ *)
  vb_Program_Init : BOOL;  (* プログラム実行前初期化 *)
  vb_Check_Input : BOOL;  (* 入力範囲判定 *)
  vb_Check_Cmd : BOOL;  (* 受信コマンドチェック *)
  vb_UID_Cmd : BOOL;  (* UIDコマンド受信 *)
  vb_EPC_Cmd : BOOL;  (* EPCコマンド受信 *)
  vb_Other_Cmd : BOOL;  (* Otherコマンド受信 *)
  vb_Program_End : BOOL;  (* FB終了処理 *)
  vb_Receiving : BOOL;  (* 受信中フラグ *)
  vw_ZTmp1 : INT;  (* Zデバイス1内部 *)
  vd_DTmp1 : DINT;  (* 内部Dデバイス1 *)
  vd_DTmp2 : DINT;  (* 内部Dデバイス2 *)
  vd_DTmp3 : DINT;  (* 内部Dデバイス3 *)
  vd_DTmp4 : DINT;  (* 内部Dデバイス4 *)
  vba_Rcv : ARRAY [0..2] OF BOOL;  (* 受信処理 *)
  vb_Rcv_End : BOOL;  (* 受信処理終了 *)
  vb_Fin_Rcv : BOOL;  (* コマンド全データ受信終了 *)
  vd_Rcv_Pos : DINT;  (* 受信バッファ読出し位置 *)
  vwa_Rcv_Buf : ARRAY [0..130] OF INT;  (* 受信バッファ(ワード単位) *)
  vwa_Rcv_Data_Byte : ARRAY [0..261] OF INT;  (* 受信バッファ(バイト単位) *)
  vw_Received_Len : INT;  (* 受信済みデータ長 *)
  vw_Trans_Len : INT;  (* 受信データ長 *)
  vw_Fin_Rcv_Len : INT;  (* 受信データ長計算用 *)
  vw_Sum_Len : INT;  (* サム値計算用データ長 *)
  vw_Rcv_Sum : INT;  (* 受信サム値 *)
  vw_Channel_No_Tmp : INT;  (* 入力チャンネル内部 *)
  vw_Start_IO_No_Tmp : INT;  (* ユニット装着XYアドレス内部 *)
  vwa_Ctrl_Data : ARRAY [0..3] OF INT;  (* ダミーコントロールデータ *)
  vd_Calc_Dword : DINT;  (* ダブルワード計算用 *)
  vw_Etx_Ofs : INT;  (* ETXオフセット *)
  vw_Chk_TID_Len : INT;  (* TIDデータ長計算用 *)
END_VAR
VAR_INPUT
  iw_Channel_No : INT;  (* 入力チャンネル *)
END_VAR
VAR
  vw_ZTmp2 : INT;  (* Zデバイス2内部 *)
  vwa_Chk_Sum : ARRAY [0..1] OF INT;  (* サム計算値 *)
END_VAR
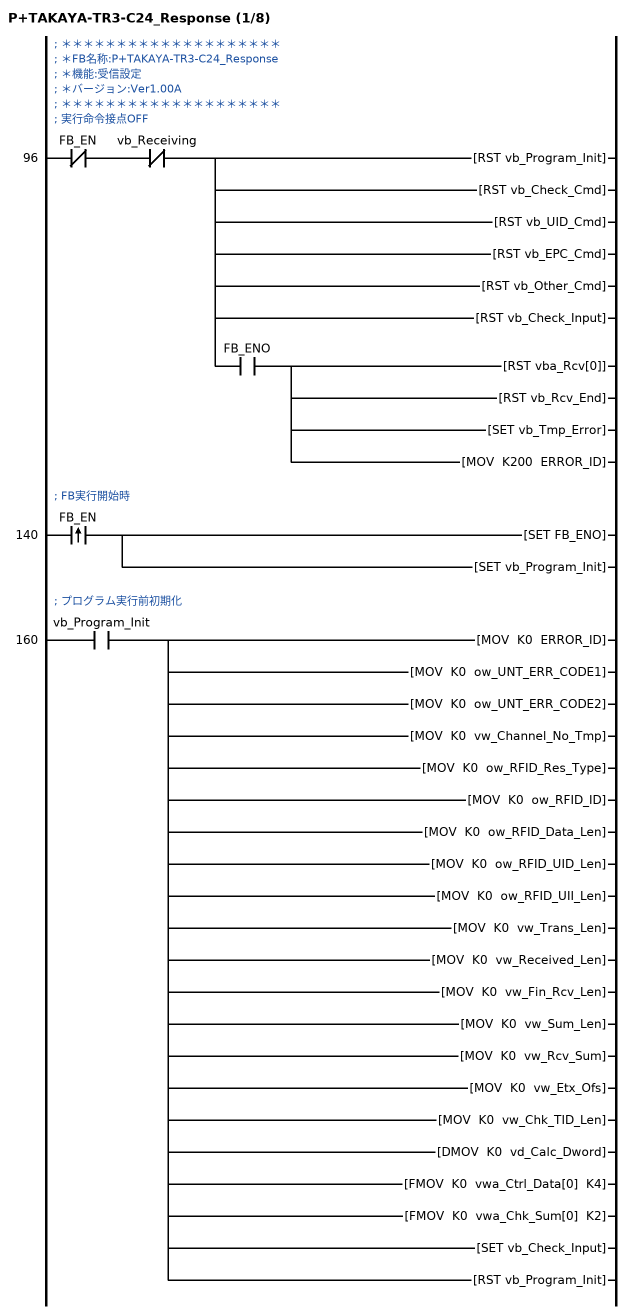
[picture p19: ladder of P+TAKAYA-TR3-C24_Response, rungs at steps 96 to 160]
; ＊＊＊＊＊＊＊＊＊＊＊＊＊＊＊＊＊＊＊＊
; ＊FB名称:P+TAKAYA-TR3-C24_Response
; ＊機能:受信設定
; ＊バージョン:Ver1.00A
; ＊＊＊＊＊＊＊＊＊＊＊＊＊＊＊＊＊＊＊＊
; 実行命令接点OFF
96    LDI     FB_EN
      ANI     vb_Receiving
      RST     vb_Program_Init
      RST     vb_Check_Cmd
      RST     vb_UID_Cmd
      RST     vb_EPC_Cmd
      RST     vb_Other_Cmd
      RST     vb_Check_Input
      AND     FB_ENO
      RST     vba_Rcv[0]
        [note] FB実行中強制終了
      RST     vb_Rcv_End
      SET     vb_Tmp_Error
      MOV     K200 ERROR_ID
; FB実行開始時
140   LDP     FB_EN
      SET     FB_ENO
      SET     vb_Program_Init
; プログラム実行前初期化
160   LD      vb_Program_Init
      MOV     K0 ERROR_ID
      MOV     K0 ow_UNT_ERR_CODE1
      MOV     K0 ow_UNT_ERR_CODE2
      MOV     K0 vw_Channel_No_Tmp
      MOV     K0 ow_RFID_Res_Type
      MOV     K0 ow_RFID_ID
      MOV     K0 ow_RFID_Data_Len
      MOV     K0 ow_RFID_UID_Len
      MOV     K0 ow_RFID_UII_Len
      MOV     K0 vw_Trans_Len
      MOV     K0 vw_Received_Len
      MOV     K0 vw_Fin_Rcv_Len
      MOV     K0 vw_Sum_Len
      MOV     K0 vw_Rcv_Sum
      MOV     K0 vw_Etx_Ofs
      MOV     K0 vw_Chk_TID_Len
      DMOV    K0 vd_Calc_Dword
      FMOV    K0 vwa_Ctrl_Data[0] K4
      FMOV    K0 vwa_Chk_Sum[0] K2
      SET     vb_Check_Input
      RST     vb_Program_Init
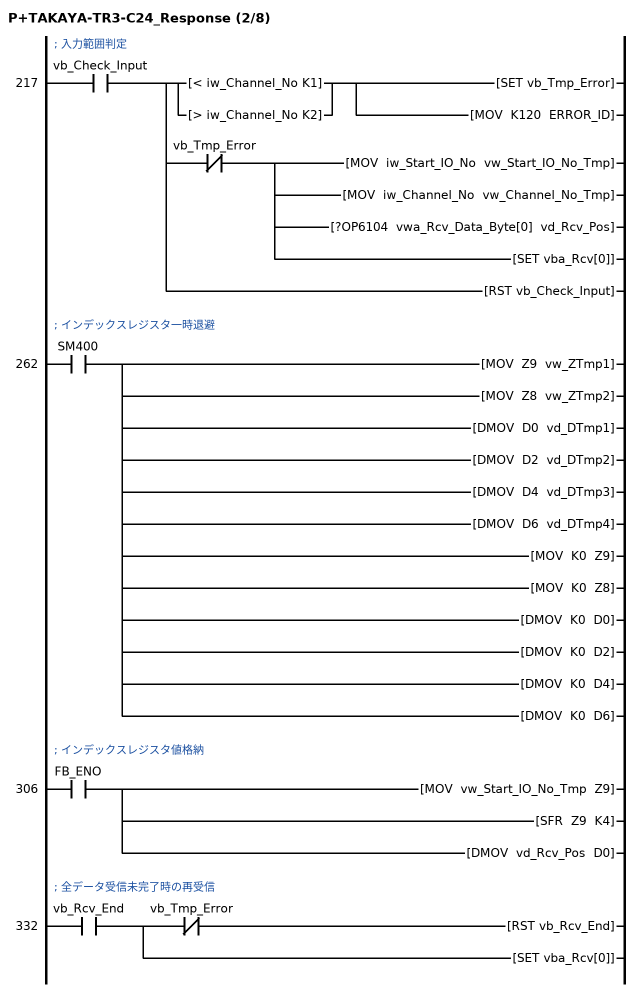
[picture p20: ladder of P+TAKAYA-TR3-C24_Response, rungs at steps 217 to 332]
; 入力範囲判定
217   LD      vb_Check_Input
      MPS
      LD<     iw_Channel_No K1
      OR>     iw_Channel_No K2
      ANB
      SET     vb_Tmp_Error
      MOV     K120 ERROR_ID
      MRD
      ANI     vb_Tmp_Error
      MOV     iw_Start_IO_No vw_Start_IO_No_Tmp
      MOV     iw_Channel_No vw_Channel_No_Tmp
      ?OP6104 vwa_Rcv_Data_Byte[0] vd_Rcv_Pos
      SET     vba_Rcv[0]
      MPP
      RST     vb_Check_Input
; インデックスレジスタ一時退避
262   LD      SM400
      MOV     Z9 vw_ZTmp1
      MOV     Z8 vw_ZTmp2
      DMOV    D0 vd_DTmp1
      DMOV    D2 vd_DTmp2
      DMOV    D4 vd_DTmp3
      DMOV    D6 vd_DTmp4
      MOV     K0 Z9
      MOV     K0 Z8
      DMOV    K0 D0
      DMOV    K0 D2
      DMOV    K0 D4
      DMOV    K0 D6
; インデックスレジスタ値格納
306   LD      FB_ENO
      MOV     vw_Start_IO_No_Tmp Z9
      SFR     Z9 K4
      DMOV    vd_Rcv_Pos D0
; 全データ受信未完了時の再受信
332   LD      vb_Rcv_End
      MPS
      ANI     vb_Tmp_Error
      RST     vb_Rcv_End
      MPP
      SET     vba_Rcv[0]
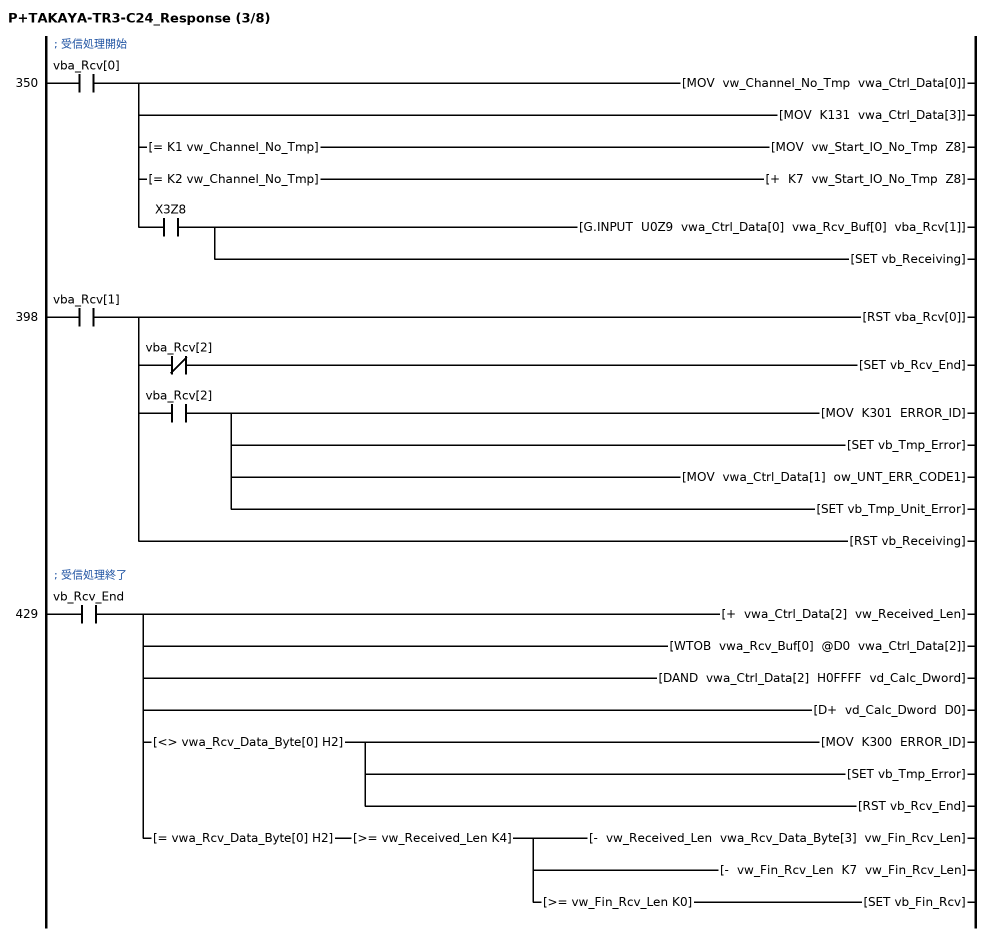
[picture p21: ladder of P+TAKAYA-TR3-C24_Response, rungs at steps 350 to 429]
; 受信処理開始
350   LD      vba_Rcv[0]
      MOV     vw_Channel_No_Tmp vwa_Ctrl_Data[0]
      MOV     K131 vwa_Ctrl_Data[3]
        [note] 受信データの許容ワード数
      MPS
      AND=    K1 vw_Channel_No_Tmp
      MOV     vw_Start_IO_No_Tmp Z8
      MRD
      AND=    K2 vw_Channel_No_Tmp
      +       K7 vw_Start_IO_No_Tmp Z8
      MPP
      AND     X3Z8
      G.INPUT U0Z9 vwa_Ctrl_Data[0] vwa_Rcv_Buf[0] vba_Rcv[1]
      SET     vb_Receiving
398   LD      vba_Rcv[1]
      RST     vba_Rcv[0]
      MPS
      ANI     vba_Rcv[2]
      SET     vb_Rcv_End
      MRD
      AND     vba_Rcv[2]
      MOV     K301 ERROR_ID
      SET     vb_Tmp_Error
      MOV     vwa_Ctrl_Data[1] ow_UNT_ERR_CODE1
      SET     vb_Tmp_Unit_Error
      MPP
      RST     vb_Receiving
; 受信処理終了
429   LD      vb_Rcv_End
      +       vwa_Ctrl_Data[2] vw_Received_Len
      WTOB    vwa_Rcv_Buf[0] @D0 vwa_Ctrl_Data[2]
      DAND    vwa_Ctrl_Data[2] H0FFFF vd_Calc_Dword
      D+      vd_Calc_Dword D0
      MPS
      AND<>   vwa_Rcv_Data_Byte[0] H2
      MOV     K300 ERROR_ID
      SET     vb_Tmp_Error
      RST     vb_Rcv_End
      MPP
      AND=    vwa_Rcv_Data_Byte[0] H2
      AND>=   vw_Received_Len K4
      -       vw_Received_Len vwa_Rcv_Data_Byte[3] vw_Fin_Rcv_Len
      -       vw_Fin_Rcv_Len K7 vw_Fin_Rcv_Len
      AND>=   vw_Fin_Rcv_Len K0
      SET     vb_Fin_Rcv
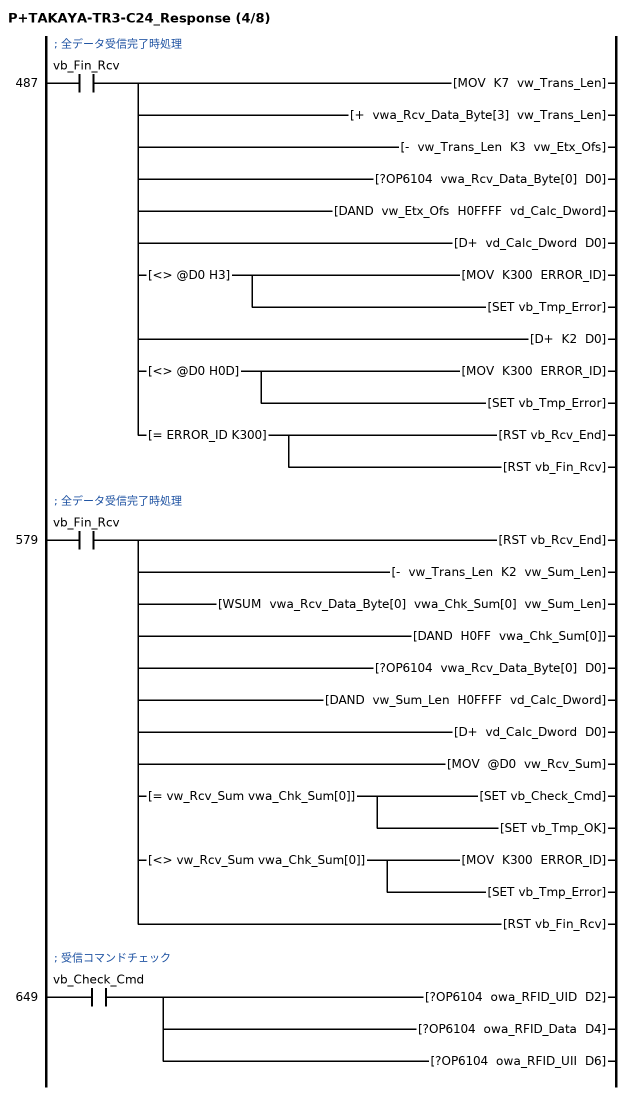
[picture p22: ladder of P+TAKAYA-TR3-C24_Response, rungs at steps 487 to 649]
; 全データ受信完了時処理
487   LD      vb_Fin_Rcv
      MOV     K7 vw_Trans_Len
      +       vwa_Rcv_Data_Byte[3] vw_Trans_Len
      -       vw_Trans_Len K3 vw_Etx_Ofs
      ?OP6104 vwa_Rcv_Data_Byte[0] D0
      DAND    vw_Etx_Ofs H0FFFF vd_Calc_Dword
      D+      vd_Calc_Dword D0
      MPS
      AND<>   @D0 H3
      MOV     K300 ERROR_ID
        [note] ETX値確認
      SET     vb_Tmp_Error
      MPP
      D+      K2 D0
        [note] CR値 =ETX値 + 2ワード
      MPS
      AND<>   @D0 H0D
      MOV     K300 ERROR_ID
        [note] CR値確認
      SET     vb_Tmp_Error
      MPP
      AND=    ERROR_ID K300
      RST     vb_Rcv_End
      RST     vb_Fin_Rcv
; 全データ受信完了時処理
579   LD      vb_Fin_Rcv
      RST     vb_Rcv_End
      -       vw_Trans_Len K2 vw_Sum_Len
        [note] SUMチェック処理
      WSUM    vwa_Rcv_Data_Byte[0] vwa_Chk_Sum[0] vw_Sum_Len
      DAND    H0FF vwa_Chk_Sum[0]
      ?OP6104 vwa_Rcv_Data_Byte[0] D0
      DAND    vw_Sum_Len H0FFFF vd_Calc_Dword
      D+      vd_Calc_Dword D0
      MOV     @D0 vw_Rcv_Sum
      MPS
      AND=    vw_Rcv_Sum vwa_Chk_Sum[0]
      SET     vb_Check_Cmd
      SET     vb_Tmp_OK
      MRD
      AND<>   vw_Rcv_Sum vwa_Chk_Sum[0]
      MOV     K300 ERROR_ID
      SET     vb_Tmp_Error
      MPP
      RST     vb_Fin_Rcv
; 受信コマンドチェック
649   LD      vb_Check_Cmd
      ?OP6104 owa_RFID_UID D2
      ?OP6104 owa_RFID_Data D4
      ?OP6104 owa_RFID_UII D6
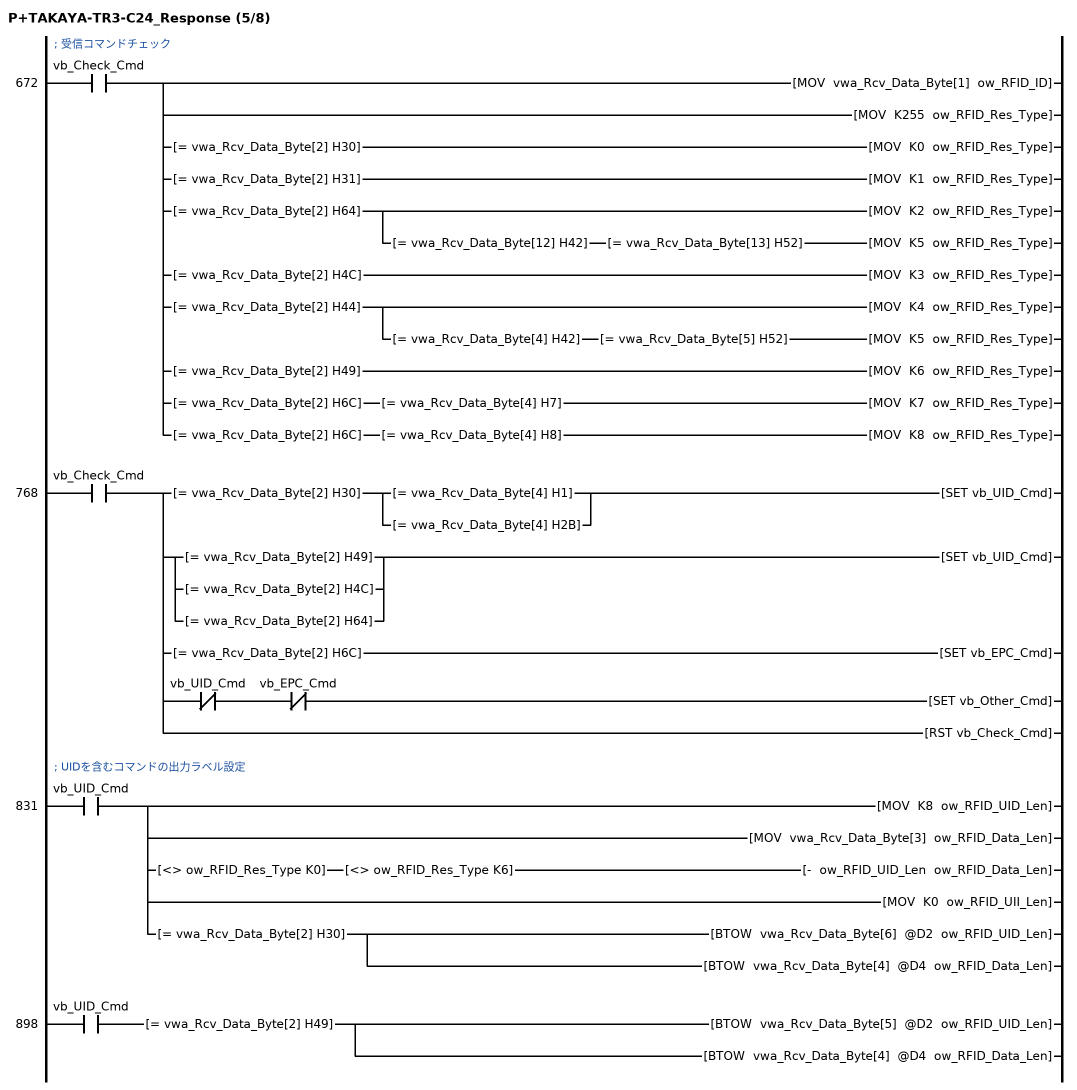
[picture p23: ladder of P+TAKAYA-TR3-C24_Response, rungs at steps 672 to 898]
; 受信コマンドチェック
672   LD      vb_Check_Cmd
      MOV     vwa_Rcv_Data_Byte[1] ow_RFID_ID
        [note] 受信IDの設定
      MOV     K255 ow_RFID_Res_Type
        [note] 受信動作タイプの設定
      MPS
      AND=    vwa_Rcv_Data_Byte[2] H30
      MOV     K0 ow_RFID_Res_Type
      MRD
      AND=    vwa_Rcv_Data_Byte[2] H31
      MOV     K1 ow_RFID_Res_Type
      MRD
      AND=    vwa_Rcv_Data_Byte[2] H64
      MOV     K2 ow_RFID_Res_Type
      AND=    vwa_Rcv_Data_Byte[12] H42
      AND=    vwa_Rcv_Data_Byte[13] H52
      MOV     K5 ow_RFID_Res_Type
      MRD
      AND=    vwa_Rcv_Data_Byte[2] H4C
      MOV     K3 ow_RFID_Res_Type
      MRD
      AND=    vwa_Rcv_Data_Byte[2] H44
      MOV     K4 ow_RFID_Res_Type
      AND=    vwa_Rcv_Data_Byte[4] H42
      AND=    vwa_Rcv_Data_Byte[5] H52
      MOV     K5 ow_RFID_Res_Type
      MRD
      AND=    vwa_Rcv_Data_Byte[2] H49
      MOV     K6 ow_RFID_Res_Type
      MRD
      AND=    vwa_Rcv_Data_Byte[2] H6C
      AND=    vwa_Rcv_Data_Byte[4] H7
      MOV     K7 ow_RFID_Res_Type
      MPP
      AND=    vwa_Rcv_Data_Byte[2] H6C
      AND=    vwa_Rcv_Data_Byte[4] H8
      MOV     K8 ow_RFID_Res_Type
768   LD      vb_Check_Cmd
      MPS
      AND=    vwa_Rcv_Data_Byte[2] H30
      LD=     vwa_Rcv_Data_Byte[4] H1
      OR=     vwa_Rcv_Data_Byte[4] H2B
      ANB
      SET     vb_UID_Cmd
      MRD
      LD=     vwa_Rcv_Data_Byte[2] H49
      OR=     vwa_Rcv_Data_Byte[2] H4C
      OR=     vwa_Rcv_Data_Byte[2] H64
      ANB
      SET     vb_UID_Cmd
      MRD
      AND=    vwa_Rcv_Data_Byte[2] H6C
      SET     vb_EPC_Cmd
      MRD
      ANI     vb_UID_Cmd
      ANI     vb_EPC_Cmd
      SET     vb_Other_Cmd
      MPP
      RST     vb_Check_Cmd
; UIDを含むコマンドの出力ラベル設定
831   LD      vb_UID_Cmd
      MOV     K8 ow_RFID_UID_Len
        [note] 受信UIDバイト数の設定
      MOV     vwa_Rcv_Data_Byte[3] ow_RFID_Data_Len
        [note] 受信バイト数の設定
      MPS
      AND<>   ow_RFID_Res_Type K0
      AND<>   ow_RFID_Res_Type K6
      -       ow_RFID_UID_Len ow_RFID_Data_Len
      MPP
      MOV     K0 ow_RFID_UII_Len
        [note] 受信UIIバイト数の設定
      AND=    vwa_Rcv_Data_Byte[2] H30
      BTOW    vwa_Rcv_Data_Byte[6] @D2 ow_RFID_UID_Len
      BTOW    vwa_Rcv_Data_Byte[4] @D4 ow_RFID_Data_Len
898   LD      vb_UID_Cmd
      AND=    vwa_Rcv_Data_Byte[2] H49
      BTOW    vwa_Rcv_Data_Byte[5] @D2 ow_RFID_UID_Len
      BTOW    vwa_Rcv_Data_Byte[4] @D4 ow_RFID_Data_Len
911   LD      vb_UID_Cmd
      MPS
      LD=     vwa_Rcv_Data_Byte[2] H4C
      OR=     vwa_Rcv_Data_Byte[2] H64
      ANB
      BTOW    vwa_Rcv_Data_Byte[4] @D2 ow_RFID_UID_Len
      BTOW    vwa_Rcv_Data_Byte[12] @D4 ow_RFID_Data_Len
      MPP
      RST     vb_UID_Cmd
; EPCコマンドの出力ラベル設定
948   LD      vb_EPC_Cmd
      MOV     vwa_Rcv_Data_Byte[5] ow_RFID_UII_Len
      BTOW    vwa_Rcv_Data_Byte[6] @D6 ow_RFID_UII_Len
      AND=    vwa_Rcv_Data_Byte[4] H7
      MOV     K0 ow_RFID_UID_Len
        [note] 受信UIDバイト数の設定
      MOV     K0 ow_RFID_Data_Len
        [note] 受信バイト数の設定
987   LD      vb_EPC_Cmd
      AND=    vwa_Rcv_Data_Byte[4] H8
      ?OP6104 vwa_Rcv_Data_Byte[6] D0
      DAND    ow_RFID_UII_Len H0FFFF vd_Calc_Dword
      D+      vd_Calc_Dword D0
      MOV     @D0 ow_RFID_Data_Len
      DINC    D0
      BTOW    @D0 @D4 ow_RFID_Data_Len
1012  LD      vb_EPC_Cmd
      AND=    vwa_Rcv_Data_Byte[4] H8
      +       ow_RFID_UII_Len ow_RFID_Data_Len vw_Chk_TID_Len
      +       K3 vw_Chk_TID_Len
      MPS
      AND>    vwa_Rcv_Data_Byte[3] vw_Chk_TID_Len
      DAND    ow_RFID_Data_Len H0FFFF vd_Calc_Dword
      D+      vd_Calc_Dword D0
      MOV     @D0 ow_RFID_UID_Len
      DINC    D0
      BTOW    @D0 @D2 ow_RFID_UID_Len
      MPP
      AND<=   vwa_Rcv_Data_Byte[3] vw_Chk_TID_Len
      MOV     K0 ow_RFID_UID_Len
1050  LD      vb_EPC_Cmd
      RST     vb_EPC_Cmd
; UIDを含まないコマンドの出力ラベル設定
1075  LD      vb_Other_Cmd
      MOV     K0 ow_RFID_UID_Len
        [note] 受信UIDバイト数の設定
      MPS
      AND=    vwa_Rcv_Data_Byte[2] H31
      MOV     K0 ow_RFID_Data_Len
        [note] 受信バイト数の設定
      MOV     vwa_Rcv_Data_Byte[4] ow_UNT_ERR_CODE1
      AND=    vwa_Rcv_Data_Byte[4] H5
      MOV     vwa_Rcv_Data_Byte[5] ow_UNT_ERR_CODE2
      MRD
      AND<>   vwa_Rcv_Data_Byte[2] H31
      MOV     vwa_Rcv_Data_Byte[3] ow_RFID_Data_Len
        [note] 受信バイト数の設定
      MRD
      AND<>   ow_RFID_Res_Type K255
      BTOW    vwa_Rcv_Data_Byte[4] @D4 ow_RFID_Data_Len
        [note] 受信データの設定
      MRD
      AND=    ow_RFID_Res_Type K255
      +       K7 ow_RFID_Data_Len
      BTOW    vwa_Rcv_Data_Byte[0] @D4 ow_RFID_Data_Len
        [note] 受信データの設定
      MPP
      MOV     K0 ow_RFID_UII_Len
        [note] 受信UIIバイト数の設定
      RST     vb_Other_Cmd
; インデックスレジスタ復帰処理
1206  LD      SM400
      MOV     vw_ZTmp1 Z9
      MOV     vw_ZTmp2 Z8
      DMOV    D0 vd_Rcv_Pos
      DMOV    vd_DTmp1 D0
      DMOV    vd_DTmp2 D2
      DMOV    vd_DTmp3 D4
      DMOV    vd_DTmp4 D6
; FB終了処理
1228  LD      vb_Program_End
      MPS
      AND     vb_Tmp_OK
      PLS     FB_OK
      MRD
      AND     vb_Tmp_Error
      PLS     FB_ERROR
      MRD
      AND     vb_Tmp_Unit_Error
      PLS     ob_UNIT_ERROR
      MPP
      RST     vb_Tmp_OK
      RST     vb_Tmp_Error
      RST     vb_Tmp_Unit_Error
      RST     FB_ENO
      RST     vb_Program_End
      RST     vba_Rcv[0]
      RST     vba_Rcv[1]
      RST     vba_Rcv[2]
1265  LD      vb_Tmp_OK
      OR      vb_Tmp_Error
      OR      vb_Tmp_Unit_Error
      SET     vb_Program_End
END_FUNCTION_BLOCK

FUNCTION_BLOCK P+TAKAYA-TR3-C24_SetActionMode  // リーダライタ動作モードの書き込み
VAR_INPUT
  FB_EN : BOOL;  (* 実行命令 *)
END_VAR
VAR_OUTPUT
  FB_OK : BOOL;  (* 正常完了 *)
  FB_ERROR : BOOL;  (* 異常完了フラグ *)
  ERROR_ID : INT;  (* エラーコード *)
  FB_ENO : BOOL;  (* 実行状態 *)
END_VAR
VAR
  vb_Program_Init : BOOL;  (* プログラム実行前初期化 *)
  vb_Check_Input : BOOL;  (* 入力範囲判定 *)
  vb_Tmp_Error : BOOL;  (* エラー内部フラグ *)
  vb_Tmp_OK : BOOL;  (* FB完了内部フラグ *)
  vw_Start_IO_No_Tmp : INT;  (* ユニット装着XYアドレス内部 *)
  vb_Tmp_Unit_Error : BOOL;  (* 機器エラー内部フラグ *)
  vb_Program_End : BOOL;  (* FB終了処理内部フラグ *)
END_VAR
VAR_OUTPUT
  ob_UNIT_ERROR : BOOL;  (* 機器異常完了フラグ *)
  ow_UNIT_ERR_CODE : INT;  (* 機器エラーコード *)
END_VAR
VAR
  vwa_Control_Data : ARRAY [0..2] OF INT;  (* コントロールデータ *)
  vb_Sum_Calc : BOOL;  (* SUM計算開始フラグ *)
  vb_Send_Ready : BOOL;  (* 送信準備完了フラグ *)
  vwa_Send_Sum : ARRAY [0..1] OF INT;  (* 送信SUM合計値 *)
  vwa_Buff_Send_Byte : ARRAY [0..10] OF INT;  (* 送信バッファバイト *)
  vba_Send : ARRAY [0..2] OF BOOL;  (* 送信処理フラグ *)
END_VAR
VAR_INPUT
  iw_Mode : INT;  (* 動作モード *)
END_VAR
VAR
  vw_Mode_Parameter_Tmp : INT;  (* モード設定パラメータ *)
END_VAR
VAR_INPUT
  ib_Anticollision : BOOL;  (* アンチコリジョン *)
  ib_Reading_Ope : BOOL;  (* 読み取り動作 *)
  ib_Buzzer : BOOL;  (* ブザー *)
  ib_Send_Data : BOOL;  (* 送信データ *)
END_VAR
VAR
  vb_Mode_Parameter : BOOL;  (* モード設定 *)
  vw_Mode_Tmp : INT;  (* 動作モード内部 *)
  vb_Check_Mode : BOOL;  (* 動作モード入力チェック *)
  vb_Join_Byte : BOOL;  (* バイト単位結合 *)
  vwa_Buff_Send_Word : ARRAY [0..5] OF INT;  (* 送信バッファワード *)
END_VAR
VAR_INPUT
  iw_Start_IO_No : INT;  (* ユニット装着XYアドレス *)
  iw_Channel_No : INT;  (* 入力チャンネル *)
END_VAR
VAR
  vw_Channel_No_Tmp : INT;  (* 入力チャンネル内部 *)
  vw_ZTmp1 : INT;  (* Zデバイス1内部 *)
  vb_Make_Control_Data : BOOL;  (* コントロールデータ生成 *)
END_VAR
; ＊＊＊＊＊＊＊＊＊＊＊＊＊＊＊＊＊＊＊＊
; ＊FB名称:P+TAKAYA-TR3-C24_SetActionMode
; ＊機能:リーダライタ動作モードの書き込み
; ＊バージョン:Ver1.00A
; ＊＊＊＊＊＊＊＊＊＊＊＊＊＊＊＊＊＊＊＊
; FB非実行時接点OFF
112   LDI     FB_EN
      RST     vb_Program_Init
      RST     vb_Check_Input
      RST     vb_Join_Byte
      RST     vb_Mode_Parameter
      RST     vb_Sum_Calc
      RST     vb_Make_Control_Data
      RST     vb_Send_Ready
      RST     vb_Check_Mode
; FB実行開始時
138   LDP     FB_EN
      SET     FB_ENO
      SET     vb_Program_Init
; プログラム実行前初期化
158   LD      vb_Program_Init
      MOV     K0 ERROR_ID
      MOV     K0 ow_UNIT_ERR_CODE
      MOV     K0 vw_Channel_No_Tmp
      MOV     K0 vw_Mode_Parameter_Tmp
      MOV     K0 vw_Mode_Tmp
      FMOV    K0 vwa_Buff_Send_Byte[0] K11
      FMOV    K0 vwa_Buff_Send_Word[0] K6
      FMOV    K0 vwa_Control_Data[0] K3
      FMOV    K0 vwa_Send_Sum[0] K2
      SET     vb_Check_Input
      RST     vb_Program_Init
; 入力範囲判定
198   LD      vb_Check_Input
      MPS
      LD<     iw_Channel_No K1
      OR>     iw_Channel_No K2
      ANB
      SET     vb_Tmp_Error
      MOV     K120 ERROR_ID
      MRD
      LD=     iw_Mode H50
      OR=     iw_Mode H58
      OR=     iw_Mode H63
      OR=     iw_Mode H64
      ANB
      SET     vb_Check_Mode
      MRD
      LD<     iw_Mode H0
      OR>     iw_Mode H1
      ANB
      ANI     vb_Check_Mode
      SET     vb_Tmp_Error
      MOV     K109 ERROR_ID
      MRD
      ANI     vb_Tmp_Error
      MOV     iw_Channel_No vw_Channel_No_Tmp
      MOV     iw_Start_IO_No vw_Start_IO_No_Tmp
      MOV     iw_Mode vw_Mode_Tmp
      SET     vba_Send[0]
      MPP
      RST     vb_Check_Input
; インデックスレジスタ一時退避
272   LD      SM400
      MOV     Z9 vw_ZTmp1
      MOV     K0 Z9
; インデックスレジスタ値格納
292   LD      FB_ENO
      MOV     vw_Start_IO_No_Tmp Z9
      SFR     Z9 K4
; 送信フォーマット作成
312   LD      vba_Send[0]
      MOV     H2 vwa_Buff_Send_Byte[0]
      MOV     H0 vwa_Buff_Send_Byte[1]
      MOV     H4E vwa_Buff_Send_Byte[2]
      MOV     H4 vwa_Buff_Send_Byte[3]
      MOV     H0 vwa_Buff_Send_Byte[4]
      MOV     vw_Mode_Tmp vwa_Buff_Send_Byte[5]
      MOV     H0 vwa_Buff_Send_Byte[6]
      MOV     H3 vwa_Buff_Send_Byte[8]
      MOV     H0D vwa_Buff_Send_Byte[10]
      SET     vb_Mode_Parameter
      RST     vba_Send[0]
; モード設定
343   LD      vb_Mode_Parameter
      MPS
      AND     ib_Anticollision
      BSET    vw_Mode_Parameter_Tmp K2
      MRD
      AND     ib_Reading_Ope
      BSET    vw_Mode_Parameter_Tmp K3
      MRD
      AND     ib_Buzzer
      BSET    vw_Mode_Parameter_Tmp K4
      MRD
      AND     ib_Send_Data
      BSET    vw_Mode_Parameter_Tmp K5
      MPP
      MOV     vw_Mode_Parameter_Tmp vwa_Buff_Send_Byte[7]
      SET     vb_Sum_Calc
      RST     vb_Mode_Parameter
; SUMの計算
383   LD      vb_Sum_Calc
      WSUM    vwa_Buff_Send_Byte[0] vwa_Send_Sum[0] K9
      DAND    H0FF vwa_Send_Sum[0]
      MOV     vwa_Send_Sum[0] vwa_Buff_Send_Byte[9]
      SET     vb_Join_Byte
      RST     vb_Sum_Calc
; バイト単位データ結合
411   LD      vb_Join_Byte
      BTOW    vwa_Buff_Send_Byte[0] vwa_Buff_Send_Word[0] K11
      SET     vb_Make_Control_Data
      RST     vb_Join_Byte
; コントロールデータ生成
434   LD      vb_Make_Control_Data
      MOV     vw_Channel_No_Tmp vwa_Control_Data[0]
      MOV     K11 vwa_Control_Data[2]
      SET     vb_Send_Ready
      RST     vb_Make_Control_Data
; 送信処理
450   LD      vb_Send_Ready
      GP.OUTPUT U0Z9 vwa_Control_Data[0] vwa_Buff_Send_Word[0] vba_Send[1]
; 正常完了かチェック
474   LD      vba_Send[1]
      MPS
      ANI     vba_Send[2]
      SET     vb_Tmp_OK
      MRD
      AND     vba_Send[2]
      MOV     K119 ERROR_ID
      SET     vb_Tmp_Error
      MOV     vwa_Control_Data[1] ow_UNIT_ERR_CODE
      SET     vb_Tmp_Unit_Error
      MPP
      RST     vb_Send_Ready
; インデックスレジスタ復帰処理
511   LD      SM400
      MOV     vw_ZTmp1 Z9
; FB完了処理
521   LD      vb_Program_End
      MPS
      AND     vb_Tmp_OK
      PLS     FB_OK
      MRD
      AND     vb_Tmp_Error
      PLS     FB_ERROR
      MRD
      AND     vb_Tmp_Unit_Error
      PLS     ob_UNIT_ERROR
      MPP
      RST     vb_Tmp_OK
      RST     vb_Tmp_Error
      RST     vb_Tmp_Unit_Error
      RST     FB_ENO
      RST     vb_Program_End
      RST     vba_Send[0]
      RST     vba_Send[1]
      RST     vba_Send[2]
558   LD      vb_Tmp_OK
      OR      vb_Tmp_Error
      OR      vb_Tmp_Unit_Error
      SET     vb_Program_End
END_FUNCTION_BLOCK
